VERSION 5.7 ;
BUSBITCHARS "[]" ;
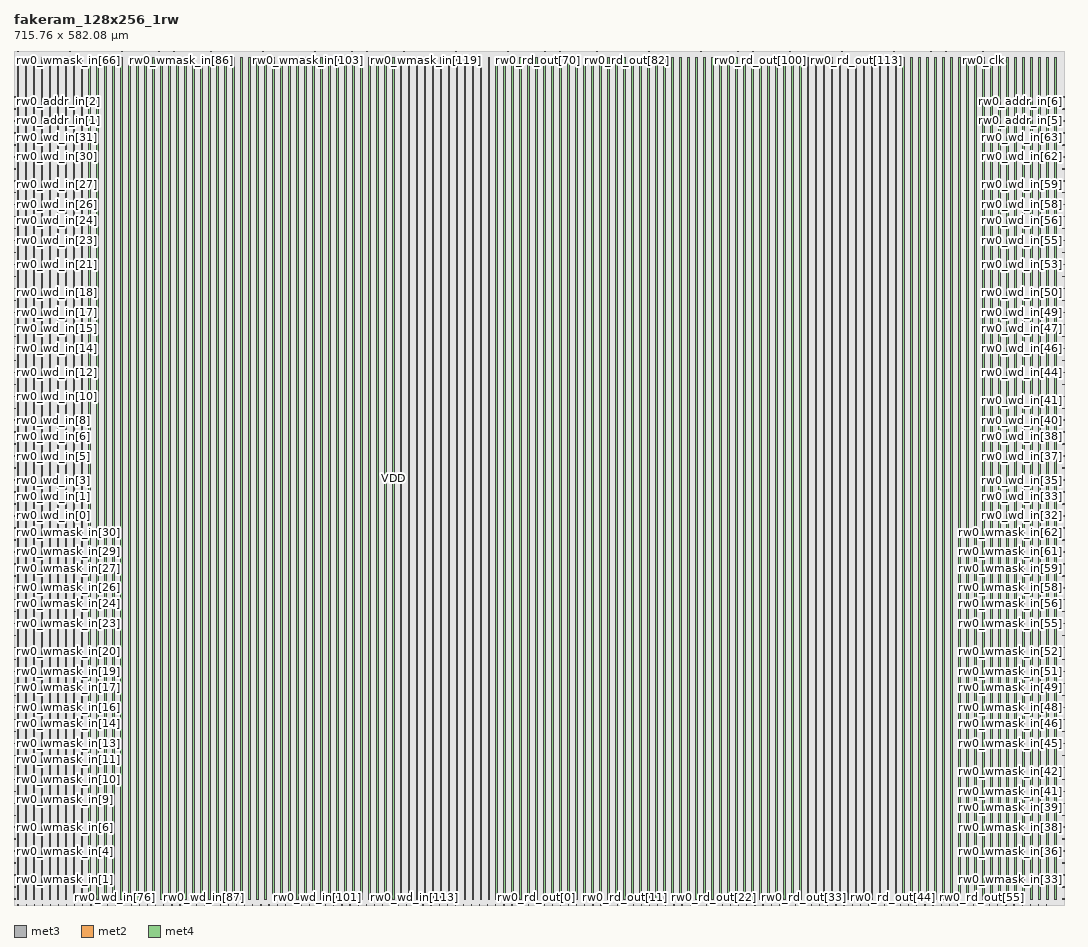
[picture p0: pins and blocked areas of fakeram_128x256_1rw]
MACRO fakeram_128x256_1rw
  FOREIGN fakeram_128x256_1rw 0 0 ;
  SYMMETRY X Y R90 ;
  SIZE 715.760 BY 582.080 ;
  CLASS BLOCK ;
  PIN rw0_wmask_in[0]
    DIRECTION INPUT ;
    USE SIGNAL ;
    SHAPE ABUTMENT ;
    PORT
      LAYER met3 ;
      RECT 0.000 3.930 0.900 4.230 ;
    END
  END rw0_wmask_in[0]
  PIN rw0_wmask_in[1]
    DIRECTION INPUT ;
    USE SIGNAL ;
    SHAPE ABUTMENT ;
    PORT
      LAYER met3 ;
      RECT 0.000 12.090 0.900 12.390 ;
    END
  END rw0_wmask_in[1]
  PIN rw0_wmask_in[2]
    DIRECTION INPUT ;
    USE SIGNAL ;
    SHAPE ABUTMENT ;
    PORT
      LAYER met3 ;
      RECT 0.000 20.250 0.900 20.550 ;
    END
  END rw0_wmask_in[2]
  PIN rw0_wmask_in[3]
    DIRECTION INPUT ;
    USE SIGNAL ;
    SHAPE ABUTMENT ;
    PORT
      LAYER met3 ;
      RECT 0.000 28.410 0.900 28.710 ;
    END
  END rw0_wmask_in[3]
  PIN rw0_wmask_in[4]
    DIRECTION INPUT ;
    USE SIGNAL ;
    SHAPE ABUTMENT ;
    PORT
      LAYER met3 ;
      RECT 0.000 36.570 0.900 36.870 ;
    END
  END rw0_wmask_in[4]
  PIN rw0_wmask_in[5]
    DIRECTION INPUT ;
    USE SIGNAL ;
    SHAPE ABUTMENT ;
    PORT
      LAYER met3 ;
      RECT 0.000 44.730 0.900 45.030 ;
    END
  END rw0_wmask_in[5]
  PIN rw0_wmask_in[6]
    DIRECTION INPUT ;
    USE SIGNAL ;
    SHAPE ABUTMENT ;
    PORT
      LAYER met3 ;
      RECT 0.000 52.890 0.900 53.190 ;
    END
  END rw0_wmask_in[6]
  PIN rw0_wmask_in[7]
    DIRECTION INPUT ;
    USE SIGNAL ;
    SHAPE ABUTMENT ;
    PORT
      LAYER met3 ;
      RECT 0.000 61.050 0.900 61.350 ;
    END
  END rw0_wmask_in[7]
  PIN rw0_wmask_in[8]
    DIRECTION INPUT ;
    USE SIGNAL ;
    SHAPE ABUTMENT ;
    PORT
      LAYER met3 ;
      RECT 0.000 69.210 0.900 69.510 ;
    END
  END rw0_wmask_in[8]
  PIN rw0_wmask_in[9]
    DIRECTION INPUT ;
    USE SIGNAL ;
    SHAPE ABUTMENT ;
    PORT
      LAYER met3 ;
      RECT 0.000 77.370 0.900 77.670 ;
    END
  END rw0_wmask_in[9]
  PIN rw0_wmask_in[10]
    DIRECTION INPUT ;
    USE SIGNAL ;
    SHAPE ABUTMENT ;
    PORT
      LAYER met3 ;
      RECT 0.000 85.530 0.900 85.830 ;
    END
  END rw0_wmask_in[10]
  PIN rw0_wmask_in[11]
    DIRECTION INPUT ;
    USE SIGNAL ;
    SHAPE ABUTMENT ;
    PORT
      LAYER met3 ;
      RECT 0.000 93.690 0.900 93.990 ;
    END
  END rw0_wmask_in[11]
  PIN rw0_wmask_in[12]
    DIRECTION INPUT ;
    USE SIGNAL ;
    SHAPE ABUTMENT ;
    PORT
      LAYER met3 ;
      RECT 0.000 101.850 0.900 102.150 ;
    END
  END rw0_wmask_in[12]
  PIN rw0_wmask_in[13]
    DIRECTION INPUT ;
    USE SIGNAL ;
    SHAPE ABUTMENT ;
    PORT
      LAYER met3 ;
      RECT 0.000 110.010 0.900 110.310 ;
    END
  END rw0_wmask_in[13]
  PIN rw0_wmask_in[14]
    DIRECTION INPUT ;
    USE SIGNAL ;
    SHAPE ABUTMENT ;
    PORT
      LAYER met3 ;
      RECT 0.000 118.170 0.900 118.470 ;
    END
  END rw0_wmask_in[14]
  PIN rw0_wmask_in[15]
    DIRECTION INPUT ;
    USE SIGNAL ;
    SHAPE ABUTMENT ;
    PORT
      LAYER met3 ;
      RECT 0.000 126.330 0.900 126.630 ;
    END
  END rw0_wmask_in[15]
  PIN rw0_wmask_in[16]
    DIRECTION INPUT ;
    USE SIGNAL ;
    SHAPE ABUTMENT ;
    PORT
      LAYER met3 ;
      RECT 0.000 134.490 0.900 134.790 ;
    END
  END rw0_wmask_in[16]
  PIN rw0_wmask_in[17]
    DIRECTION INPUT ;
    USE SIGNAL ;
    SHAPE ABUTMENT ;
    PORT
      LAYER met3 ;
      RECT 0.000 142.650 0.900 142.950 ;
    END
  END rw0_wmask_in[17]
  PIN rw0_wmask_in[18]
    DIRECTION INPUT ;
    USE SIGNAL ;
    SHAPE ABUTMENT ;
    PORT
      LAYER met3 ;
      RECT 0.000 150.810 0.900 151.110 ;
    END
  END rw0_wmask_in[18]
  PIN rw0_wmask_in[19]
    DIRECTION INPUT ;
    USE SIGNAL ;
    SHAPE ABUTMENT ;
    PORT
      LAYER met3 ;
      RECT 0.000 158.970 0.900 159.270 ;
    END
  END rw0_wmask_in[19]
  PIN rw0_wmask_in[20]
    DIRECTION INPUT ;
    USE SIGNAL ;
    SHAPE ABUTMENT ;
    PORT
      LAYER met3 ;
      RECT 0.000 167.130 0.900 167.430 ;
    END
  END rw0_wmask_in[20]
  PIN rw0_wmask_in[21]
    DIRECTION INPUT ;
    USE SIGNAL ;
    SHAPE ABUTMENT ;
    PORT
      LAYER met3 ;
      RECT 0.000 175.290 0.900 175.590 ;
    END
  END rw0_wmask_in[21]
  PIN rw0_wmask_in[22]
    DIRECTION INPUT ;
    USE SIGNAL ;
    SHAPE ABUTMENT ;
    PORT
      LAYER met3 ;
      RECT 0.000 183.450 0.900 183.750 ;
    END
  END rw0_wmask_in[22]
  PIN rw0_wmask_in[23]
    DIRECTION INPUT ;
    USE SIGNAL ;
    SHAPE ABUTMENT ;
    PORT
      LAYER met3 ;
      RECT 0.000 191.610 0.900 191.910 ;
    END
  END rw0_wmask_in[23]
  PIN rw0_wmask_in[24]
    DIRECTION INPUT ;
    USE SIGNAL ;
    SHAPE ABUTMENT ;
    PORT
      LAYER met3 ;
      RECT 0.000 199.770 0.900 200.070 ;
    END
  END rw0_wmask_in[24]
  PIN rw0_wmask_in[25]
    DIRECTION INPUT ;
    USE SIGNAL ;
    SHAPE ABUTMENT ;
    PORT
      LAYER met3 ;
      RECT 0.000 207.930 0.900 208.230 ;
    END
  END rw0_wmask_in[25]
  PIN rw0_wmask_in[26]
    DIRECTION INPUT ;
    USE SIGNAL ;
    SHAPE ABUTMENT ;
    PORT
      LAYER met3 ;
      RECT 0.000 216.090 0.900 216.390 ;
    END
  END rw0_wmask_in[26]
  PIN rw0_wmask_in[27]
    DIRECTION INPUT ;
    USE SIGNAL ;
    SHAPE ABUTMENT ;
    PORT
      LAYER met3 ;
      RECT 0.000 224.250 0.900 224.550 ;
    END
  END rw0_wmask_in[27]
  PIN rw0_wmask_in[28]
    DIRECTION INPUT ;
    USE SIGNAL ;
    SHAPE ABUTMENT ;
    PORT
      LAYER met3 ;
      RECT 0.000 232.410 0.900 232.710 ;
    END
  END rw0_wmask_in[28]
  PIN rw0_wmask_in[29]
    DIRECTION INPUT ;
    USE SIGNAL ;
    SHAPE ABUTMENT ;
    PORT
      LAYER met3 ;
      RECT 0.000 240.570 0.900 240.870 ;
    END
  END rw0_wmask_in[29]
  PIN rw0_wmask_in[30]
    DIRECTION INPUT ;
    USE SIGNAL ;
    SHAPE ABUTMENT ;
    PORT
      LAYER met3 ;
      RECT 0.000 248.730 0.900 249.030 ;
    END
  END rw0_wmask_in[30]
  PIN rw0_wmask_in[31]
    DIRECTION INPUT ;
    USE SIGNAL ;
    SHAPE ABUTMENT ;
    PORT
      LAYER met3 ;
      RECT 0.000 256.890 0.900 257.190 ;
    END
  END rw0_wmask_in[31]
  PIN rw0_wmask_in[32]
    DIRECTION INPUT ;
    USE SIGNAL ;
    SHAPE ABUTMENT ;
    PORT
      LAYER met3 ;
      RECT 714.860 3.930 715.760 4.230 ;
    END
  END rw0_wmask_in[32]
  PIN rw0_wmask_in[33]
    DIRECTION INPUT ;
    USE SIGNAL ;
    SHAPE ABUTMENT ;
    PORT
      LAYER met3 ;
      RECT 714.860 12.090 715.760 12.390 ;
    END
  END rw0_wmask_in[33]
  PIN rw0_wmask_in[34]
    DIRECTION INPUT ;
    USE SIGNAL ;
    SHAPE ABUTMENT ;
    PORT
      LAYER met3 ;
      RECT 714.860 20.250 715.760 20.550 ;
    END
  END rw0_wmask_in[34]
  PIN rw0_wmask_in[35]
    DIRECTION INPUT ;
    USE SIGNAL ;
    SHAPE ABUTMENT ;
    PORT
      LAYER met3 ;
      RECT 714.860 28.410 715.760 28.710 ;
    END
  END rw0_wmask_in[35]
  PIN rw0_wmask_in[36]
    DIRECTION INPUT ;
    USE SIGNAL ;
    SHAPE ABUTMENT ;
    PORT
      LAYER met3 ;
      RECT 714.860 36.570 715.760 36.870 ;
    END
  END rw0_wmask_in[36]
  PIN rw0_wmask_in[37]
    DIRECTION INPUT ;
    USE SIGNAL ;
    SHAPE ABUTMENT ;
    PORT
      LAYER met3 ;
      RECT 714.860 44.730 715.760 45.030 ;
    END
  END rw0_wmask_in[37]
  PIN rw0_wmask_in[38]
    DIRECTION INPUT ;
    USE SIGNAL ;
    SHAPE ABUTMENT ;
    PORT
      LAYER met3 ;
      RECT 714.860 52.890 715.760 53.190 ;
    END
  END rw0_wmask_in[38]
  PIN rw0_wmask_in[39]
    DIRECTION INPUT ;
    USE SIGNAL ;
    SHAPE ABUTMENT ;
    PORT
      LAYER met3 ;
      RECT 714.860 61.050 715.760 61.350 ;
    END
  END rw0_wmask_in[39]
  PIN rw0_wmask_in[40]
    DIRECTION INPUT ;
    USE SIGNAL ;
    SHAPE ABUTMENT ;
    PORT
      LAYER met3 ;
      RECT 714.860 69.210 715.760 69.510 ;
    END
  END rw0_wmask_in[40]
  PIN rw0_wmask_in[41]
    DIRECTION INPUT ;
    USE SIGNAL ;
    SHAPE ABUTMENT ;
    PORT
      LAYER met3 ;
      RECT 714.860 77.370 715.760 77.670 ;
    END
  END rw0_wmask_in[41]
  PIN rw0_wmask_in[42]
    DIRECTION INPUT ;
    USE SIGNAL ;
    SHAPE ABUTMENT ;
    PORT
      LAYER met3 ;
      RECT 714.860 85.530 715.760 85.830 ;
    END
  END rw0_wmask_in[42]
  PIN rw0_wmask_in[43]
    DIRECTION INPUT ;
    USE SIGNAL ;
    SHAPE ABUTMENT ;
    PORT
      LAYER met3 ;
      RECT 714.860 93.690 715.760 93.990 ;
    END
  END rw0_wmask_in[43]
  PIN rw0_wmask_in[44]
    DIRECTION INPUT ;
    USE SIGNAL ;
    SHAPE ABUTMENT ;
    PORT
      LAYER met3 ;
      RECT 714.860 101.850 715.760 102.150 ;
    END
  END rw0_wmask_in[44]
  PIN rw0_wmask_in[45]
    DIRECTION INPUT ;
    USE SIGNAL ;
    SHAPE ABUTMENT ;
    PORT
      LAYER met3 ;
      RECT 714.860 110.010 715.760 110.310 ;
    END
  END rw0_wmask_in[45]
  PIN rw0_wmask_in[46]
    DIRECTION INPUT ;
    USE SIGNAL ;
    SHAPE ABUTMENT ;
    PORT
      LAYER met3 ;
      RECT 714.860 118.170 715.760 118.470 ;
    END
  END rw0_wmask_in[46]
  PIN rw0_wmask_in[47]
    DIRECTION INPUT ;
    USE SIGNAL ;
    SHAPE ABUTMENT ;
    PORT
      LAYER met3 ;
      RECT 714.860 126.330 715.760 126.630 ;
    END
  END rw0_wmask_in[47]
  PIN rw0_wmask_in[48]
    DIRECTION INPUT ;
    USE SIGNAL ;
    SHAPE ABUTMENT ;
    PORT
      LAYER met3 ;
      RECT 714.860 134.490 715.760 134.790 ;
    END
  END rw0_wmask_in[48]
  PIN rw0_wmask_in[49]
    DIRECTION INPUT ;
    USE SIGNAL ;
    SHAPE ABUTMENT ;
    PORT
      LAYER met3 ;
      RECT 714.860 142.650 715.760 142.950 ;
    END
  END rw0_wmask_in[49]
  PIN rw0_wmask_in[50]
    DIRECTION INPUT ;
    USE SIGNAL ;
    SHAPE ABUTMENT ;
    PORT
      LAYER met3 ;
      RECT 714.860 150.810 715.760 151.110 ;
    END
  END rw0_wmask_in[50]
  PIN rw0_wmask_in[51]
    DIRECTION INPUT ;
    USE SIGNAL ;
    SHAPE ABUTMENT ;
    PORT
      LAYER met3 ;
      RECT 714.860 158.970 715.760 159.270 ;
    END
  END rw0_wmask_in[51]
  PIN rw0_wmask_in[52]
    DIRECTION INPUT ;
    USE SIGNAL ;
    SHAPE ABUTMENT ;
    PORT
      LAYER met3 ;
      RECT 714.860 167.130 715.760 167.430 ;
    END
  END rw0_wmask_in[52]
  PIN rw0_wmask_in[53]
    DIRECTION INPUT ;
    USE SIGNAL ;
    SHAPE ABUTMENT ;
    PORT
      LAYER met3 ;
      RECT 714.860 175.290 715.760 175.590 ;
    END
  END rw0_wmask_in[53]
  PIN rw0_wmask_in[54]
    DIRECTION INPUT ;
    USE SIGNAL ;
    SHAPE ABUTMENT ;
    PORT
      LAYER met3 ;
      RECT 714.860 183.450 715.760 183.750 ;
    END
  END rw0_wmask_in[54]
  PIN rw0_wmask_in[55]
    DIRECTION INPUT ;
    USE SIGNAL ;
    SHAPE ABUTMENT ;
    PORT
      LAYER met3 ;
      RECT 714.860 191.610 715.760 191.910 ;
    END
  END rw0_wmask_in[55]
  PIN rw0_wmask_in[56]
    DIRECTION INPUT ;
    USE SIGNAL ;
    SHAPE ABUTMENT ;
    PORT
      LAYER met3 ;
      RECT 714.860 199.770 715.760 200.070 ;
    END
  END rw0_wmask_in[56]
  PIN rw0_wmask_in[57]
    DIRECTION INPUT ;
    USE SIGNAL ;
    SHAPE ABUTMENT ;
    PORT
      LAYER met3 ;
      RECT 714.860 207.930 715.760 208.230 ;
    END
  END rw0_wmask_in[57]
  PIN rw0_wmask_in[58]
    DIRECTION INPUT ;
    USE SIGNAL ;
    SHAPE ABUTMENT ;
    PORT
      LAYER met3 ;
      RECT 714.860 216.090 715.760 216.390 ;
    END
  END rw0_wmask_in[58]
  PIN rw0_wmask_in[59]
    DIRECTION INPUT ;
    USE SIGNAL ;
    SHAPE ABUTMENT ;
    PORT
      LAYER met3 ;
      RECT 714.860 224.250 715.760 224.550 ;
    END
  END rw0_wmask_in[59]
  PIN rw0_wmask_in[60]
    DIRECTION INPUT ;
    USE SIGNAL ;
    SHAPE ABUTMENT ;
    PORT
      LAYER met3 ;
      RECT 714.860 232.410 715.760 232.710 ;
    END
  END rw0_wmask_in[60]
  PIN rw0_wmask_in[61]
    DIRECTION INPUT ;
    USE SIGNAL ;
    SHAPE ABUTMENT ;
    PORT
      LAYER met3 ;
      RECT 714.860 240.570 715.760 240.870 ;
    END
  END rw0_wmask_in[61]
  PIN rw0_wmask_in[62]
    DIRECTION INPUT ;
    USE SIGNAL ;
    SHAPE ABUTMENT ;
    PORT
      LAYER met3 ;
      RECT 714.860 248.730 715.760 249.030 ;
    END
  END rw0_wmask_in[62]
  PIN rw0_wmask_in[63]
    DIRECTION INPUT ;
    USE SIGNAL ;
    SHAPE ABUTMENT ;
    PORT
      LAYER met3 ;
      RECT 714.860 256.890 715.760 257.190 ;
    END
  END rw0_wmask_in[63]
  PIN rw0_wmask_in[64]
    DIRECTION INPUT ;
    USE SIGNAL ;
    SHAPE ABUTMENT ;
    PORT
      LAYER met2 ;
      RECT 2.690 581.660 2.830 582.080 ;
    END
  END rw0_wmask_in[64]
  PIN rw0_wmask_in[65]
    DIRECTION INPUT ;
    USE SIGNAL ;
    SHAPE ABUTMENT ;
    PORT
      LAYER met2 ;
      RECT 7.750 581.660 7.890 582.080 ;
    END
  END rw0_wmask_in[65]
  PIN rw0_wmask_in[66]
    DIRECTION INPUT ;
    USE SIGNAL ;
    SHAPE ABUTMENT ;
    PORT
      LAYER met2 ;
      RECT 12.810 581.660 12.950 582.080 ;
    END
  END rw0_wmask_in[66]
  PIN rw0_wmask_in[67]
    DIRECTION INPUT ;
    USE SIGNAL ;
    SHAPE ABUTMENT ;
    PORT
      LAYER met2 ;
      RECT 17.870 581.660 18.010 582.080 ;
    END
  END rw0_wmask_in[67]
  PIN rw0_wmask_in[68]
    DIRECTION INPUT ;
    USE SIGNAL ;
    SHAPE ABUTMENT ;
    PORT
      LAYER met2 ;
      RECT 22.930 581.660 23.070 582.080 ;
    END
  END rw0_wmask_in[68]
  PIN rw0_wmask_in[69]
    DIRECTION INPUT ;
    USE SIGNAL ;
    SHAPE ABUTMENT ;
    PORT
      LAYER met2 ;
      RECT 27.990 581.660 28.130 582.080 ;
    END
  END rw0_wmask_in[69]
  PIN rw0_wmask_in[70]
    DIRECTION INPUT ;
    USE SIGNAL ;
    SHAPE ABUTMENT ;
    PORT
      LAYER met2 ;
      RECT 33.050 581.660 33.190 582.080 ;
    END
  END rw0_wmask_in[70]
  PIN rw0_wmask_in[71]
    DIRECTION INPUT ;
    USE SIGNAL ;
    SHAPE ABUTMENT ;
    PORT
      LAYER met2 ;
      RECT 38.110 581.660 38.250 582.080 ;
    END
  END rw0_wmask_in[71]
  PIN rw0_wmask_in[72]
    DIRECTION INPUT ;
    USE SIGNAL ;
    SHAPE ABUTMENT ;
    PORT
      LAYER met2 ;
      RECT 43.170 581.660 43.310 582.080 ;
    END
  END rw0_wmask_in[72]
  PIN rw0_wmask_in[73]
    DIRECTION INPUT ;
    USE SIGNAL ;
    SHAPE ABUTMENT ;
    PORT
      LAYER met2 ;
      RECT 48.230 581.660 48.370 582.080 ;
    END
  END rw0_wmask_in[73]
  PIN rw0_wmask_in[74]
    DIRECTION INPUT ;
    USE SIGNAL ;
    SHAPE ABUTMENT ;
    PORT
      LAYER met2 ;
      RECT 53.290 581.660 53.430 582.080 ;
    END
  END rw0_wmask_in[74]
  PIN rw0_wmask_in[75]
    DIRECTION INPUT ;
    USE SIGNAL ;
    SHAPE ABUTMENT ;
    PORT
      LAYER met2 ;
      RECT 58.350 581.660 58.490 582.080 ;
    END
  END rw0_wmask_in[75]
  PIN rw0_wmask_in[76]
    DIRECTION INPUT ;
    USE SIGNAL ;
    SHAPE ABUTMENT ;
    PORT
      LAYER met2 ;
      RECT 63.410 581.660 63.550 582.080 ;
    END
  END rw0_wmask_in[76]
  PIN rw0_wmask_in[77]
    DIRECTION INPUT ;
    USE SIGNAL ;
    SHAPE ABUTMENT ;
    PORT
      LAYER met2 ;
      RECT 68.470 581.660 68.610 582.080 ;
    END
  END rw0_wmask_in[77]
  PIN rw0_wmask_in[78]
    DIRECTION INPUT ;
    USE SIGNAL ;
    SHAPE ABUTMENT ;
    PORT
      LAYER met2 ;
      RECT 73.530 581.660 73.670 582.080 ;
    END
  END rw0_wmask_in[78]
  PIN rw0_wmask_in[79]
    DIRECTION INPUT ;
    USE SIGNAL ;
    SHAPE ABUTMENT ;
    PORT
      LAYER met2 ;
      RECT 78.590 581.660 78.730 582.080 ;
    END
  END rw0_wmask_in[79]
  PIN rw0_wmask_in[80]
    DIRECTION INPUT ;
    USE SIGNAL ;
    SHAPE ABUTMENT ;
    PORT
      LAYER met2 ;
      RECT 83.650 581.660 83.790 582.080 ;
    END
  END rw0_wmask_in[80]
  PIN rw0_wmask_in[81]
    DIRECTION INPUT ;
    USE SIGNAL ;
    SHAPE ABUTMENT ;
    PORT
      LAYER met2 ;
      RECT 88.710 581.660 88.850 582.080 ;
    END
  END rw0_wmask_in[81]
  PIN rw0_wmask_in[82]
    DIRECTION INPUT ;
    USE SIGNAL ;
    SHAPE ABUTMENT ;
    PORT
      LAYER met2 ;
      RECT 93.770 581.660 93.910 582.080 ;
    END
  END rw0_wmask_in[82]
  PIN rw0_wmask_in[83]
    DIRECTION INPUT ;
    USE SIGNAL ;
    SHAPE ABUTMENT ;
    PORT
      LAYER met2 ;
      RECT 98.830 581.660 98.970 582.080 ;
    END
  END rw0_wmask_in[83]
  PIN rw0_wmask_in[84]
    DIRECTION INPUT ;
    USE SIGNAL ;
    SHAPE ABUTMENT ;
    PORT
      LAYER met2 ;
      RECT 103.890 581.660 104.030 582.080 ;
    END
  END rw0_wmask_in[84]
  PIN rw0_wmask_in[85]
    DIRECTION INPUT ;
    USE SIGNAL ;
    SHAPE ABUTMENT ;
    PORT
      LAYER met2 ;
      RECT 108.950 581.660 109.090 582.080 ;
    END
  END rw0_wmask_in[85]
  PIN rw0_wmask_in[86]
    DIRECTION INPUT ;
    USE SIGNAL ;
    SHAPE ABUTMENT ;
    PORT
      LAYER met2 ;
      RECT 114.010 581.660 114.150 582.080 ;
    END
  END rw0_wmask_in[86]
  PIN rw0_wmask_in[87]
    DIRECTION INPUT ;
    USE SIGNAL ;
    SHAPE ABUTMENT ;
    PORT
      LAYER met2 ;
      RECT 119.070 581.660 119.210 582.080 ;
    END
  END rw0_wmask_in[87]
  PIN rw0_wmask_in[88]
    DIRECTION INPUT ;
    USE SIGNAL ;
    SHAPE ABUTMENT ;
    PORT
      LAYER met2 ;
      RECT 124.130 581.660 124.270 582.080 ;
    END
  END rw0_wmask_in[88]
  PIN rw0_wmask_in[89]
    DIRECTION INPUT ;
    USE SIGNAL ;
    SHAPE ABUTMENT ;
    PORT
      LAYER met2 ;
      RECT 129.190 581.660 129.330 582.080 ;
    END
  END rw0_wmask_in[89]
  PIN rw0_wmask_in[90]
    DIRECTION INPUT ;
    USE SIGNAL ;
    SHAPE ABUTMENT ;
    PORT
      LAYER met2 ;
      RECT 134.250 581.660 134.390 582.080 ;
    END
  END rw0_wmask_in[90]
  PIN rw0_wmask_in[91]
    DIRECTION INPUT ;
    USE SIGNAL ;
    SHAPE ABUTMENT ;
    PORT
      LAYER met2 ;
      RECT 139.310 581.660 139.450 582.080 ;
    END
  END rw0_wmask_in[91]
  PIN rw0_wmask_in[92]
    DIRECTION INPUT ;
    USE SIGNAL ;
    SHAPE ABUTMENT ;
    PORT
      LAYER met2 ;
      RECT 144.370 581.660 144.510 582.080 ;
    END
  END rw0_wmask_in[92]
  PIN rw0_wmask_in[93]
    DIRECTION INPUT ;
    USE SIGNAL ;
    SHAPE ABUTMENT ;
    PORT
      LAYER met2 ;
      RECT 149.430 581.660 149.570 582.080 ;
    END
  END rw0_wmask_in[93]
  PIN rw0_wmask_in[94]
    DIRECTION INPUT ;
    USE SIGNAL ;
    SHAPE ABUTMENT ;
    PORT
      LAYER met2 ;
      RECT 154.490 581.660 154.630 582.080 ;
    END
  END rw0_wmask_in[94]
  PIN rw0_wmask_in[95]
    DIRECTION INPUT ;
    USE SIGNAL ;
    SHAPE ABUTMENT ;
    PORT
      LAYER met2 ;
      RECT 159.550 581.660 159.690 582.080 ;
    END
  END rw0_wmask_in[95]
  PIN rw0_wmask_in[96]
    DIRECTION INPUT ;
    USE SIGNAL ;
    SHAPE ABUTMENT ;
    PORT
      LAYER met2 ;
      RECT 164.610 581.660 164.750 582.080 ;
    END
  END rw0_wmask_in[96]
  PIN rw0_wmask_in[97]
    DIRECTION INPUT ;
    USE SIGNAL ;
    SHAPE ABUTMENT ;
    PORT
      LAYER met2 ;
      RECT 169.670 581.660 169.810 582.080 ;
    END
  END rw0_wmask_in[97]
  PIN rw0_wmask_in[98]
    DIRECTION INPUT ;
    USE SIGNAL ;
    SHAPE ABUTMENT ;
    PORT
      LAYER met2 ;
      RECT 174.730 581.660 174.870 582.080 ;
    END
  END rw0_wmask_in[98]
  PIN rw0_wmask_in[99]
    DIRECTION INPUT ;
    USE SIGNAL ;
    SHAPE ABUTMENT ;
    PORT
      LAYER met2 ;
      RECT 179.790 581.660 179.930 582.080 ;
    END
  END rw0_wmask_in[99]
  PIN rw0_wmask_in[100]
    DIRECTION INPUT ;
    USE SIGNAL ;
    SHAPE ABUTMENT ;
    PORT
      LAYER met2 ;
      RECT 184.850 581.660 184.990 582.080 ;
    END
  END rw0_wmask_in[100]
  PIN rw0_wmask_in[101]
    DIRECTION INPUT ;
    USE SIGNAL ;
    SHAPE ABUTMENT ;
    PORT
      LAYER met2 ;
      RECT 189.910 581.660 190.050 582.080 ;
    END
  END rw0_wmask_in[101]
  PIN rw0_wmask_in[102]
    DIRECTION INPUT ;
    USE SIGNAL ;
    SHAPE ABUTMENT ;
    PORT
      LAYER met2 ;
      RECT 194.970 581.660 195.110 582.080 ;
    END
  END rw0_wmask_in[102]
  PIN rw0_wmask_in[103]
    DIRECTION INPUT ;
    USE SIGNAL ;
    SHAPE ABUTMENT ;
    PORT
      LAYER met2 ;
      RECT 200.030 581.660 200.170 582.080 ;
    END
  END rw0_wmask_in[103]
  PIN rw0_wmask_in[104]
    DIRECTION INPUT ;
    USE SIGNAL ;
    SHAPE ABUTMENT ;
    PORT
      LAYER met2 ;
      RECT 205.090 581.660 205.230 582.080 ;
    END
  END rw0_wmask_in[104]
  PIN rw0_wmask_in[105]
    DIRECTION INPUT ;
    USE SIGNAL ;
    SHAPE ABUTMENT ;
    PORT
      LAYER met2 ;
      RECT 210.150 581.660 210.290 582.080 ;
    END
  END rw0_wmask_in[105]
  PIN rw0_wmask_in[106]
    DIRECTION INPUT ;
    USE SIGNAL ;
    SHAPE ABUTMENT ;
    PORT
      LAYER met2 ;
      RECT 215.210 581.660 215.350 582.080 ;
    END
  END rw0_wmask_in[106]
  PIN rw0_wmask_in[107]
    DIRECTION INPUT ;
    USE SIGNAL ;
    SHAPE ABUTMENT ;
    PORT
      LAYER met2 ;
      RECT 220.270 581.660 220.410 582.080 ;
    END
  END rw0_wmask_in[107]
  PIN rw0_wmask_in[108]
    DIRECTION INPUT ;
    USE SIGNAL ;
    SHAPE ABUTMENT ;
    PORT
      LAYER met2 ;
      RECT 225.330 581.660 225.470 582.080 ;
    END
  END rw0_wmask_in[108]
  PIN rw0_wmask_in[109]
    DIRECTION INPUT ;
    USE SIGNAL ;
    SHAPE ABUTMENT ;
    PORT
      LAYER met2 ;
      RECT 230.390 581.660 230.530 582.080 ;
    END
  END rw0_wmask_in[109]
  PIN rw0_wmask_in[110]
    DIRECTION INPUT ;
    USE SIGNAL ;
    SHAPE ABUTMENT ;
    PORT
      LAYER met2 ;
      RECT 235.450 581.660 235.590 582.080 ;
    END
  END rw0_wmask_in[110]
  PIN rw0_wmask_in[111]
    DIRECTION INPUT ;
    USE SIGNAL ;
    SHAPE ABUTMENT ;
    PORT
      LAYER met2 ;
      RECT 240.510 581.660 240.650 582.080 ;
    END
  END rw0_wmask_in[111]
  PIN rw0_wmask_in[112]
    DIRECTION INPUT ;
    USE SIGNAL ;
    SHAPE ABUTMENT ;
    PORT
      LAYER met2 ;
      RECT 245.570 581.660 245.710 582.080 ;
    END
  END rw0_wmask_in[112]
  PIN rw0_wmask_in[113]
    DIRECTION INPUT ;
    USE SIGNAL ;
    SHAPE ABUTMENT ;
    PORT
      LAYER met2 ;
      RECT 250.630 581.660 250.770 582.080 ;
    END
  END rw0_wmask_in[113]
  PIN rw0_wmask_in[114]
    DIRECTION INPUT ;
    USE SIGNAL ;
    SHAPE ABUTMENT ;
    PORT
      LAYER met2 ;
      RECT 255.690 581.660 255.830 582.080 ;
    END
  END rw0_wmask_in[114]
  PIN rw0_wmask_in[115]
    DIRECTION INPUT ;
    USE SIGNAL ;
    SHAPE ABUTMENT ;
    PORT
      LAYER met2 ;
      RECT 260.750 581.660 260.890 582.080 ;
    END
  END rw0_wmask_in[115]
  PIN rw0_wmask_in[116]
    DIRECTION INPUT ;
    USE SIGNAL ;
    SHAPE ABUTMENT ;
    PORT
      LAYER met2 ;
      RECT 265.810 581.660 265.950 582.080 ;
    END
  END rw0_wmask_in[116]
  PIN rw0_wmask_in[117]
    DIRECTION INPUT ;
    USE SIGNAL ;
    SHAPE ABUTMENT ;
    PORT
      LAYER met2 ;
      RECT 270.870 581.660 271.010 582.080 ;
    END
  END rw0_wmask_in[117]
  PIN rw0_wmask_in[118]
    DIRECTION INPUT ;
    USE SIGNAL ;
    SHAPE ABUTMENT ;
    PORT
      LAYER met2 ;
      RECT 275.930 581.660 276.070 582.080 ;
    END
  END rw0_wmask_in[118]
  PIN rw0_wmask_in[119]
    DIRECTION INPUT ;
    USE SIGNAL ;
    SHAPE ABUTMENT ;
    PORT
      LAYER met2 ;
      RECT 280.990 581.660 281.130 582.080 ;
    END
  END rw0_wmask_in[119]
  PIN rw0_wmask_in[120]
    DIRECTION INPUT ;
    USE SIGNAL ;
    SHAPE ABUTMENT ;
    PORT
      LAYER met2 ;
      RECT 286.050 581.660 286.190 582.080 ;
    END
  END rw0_wmask_in[120]
  PIN rw0_wmask_in[121]
    DIRECTION INPUT ;
    USE SIGNAL ;
    SHAPE ABUTMENT ;
    PORT
      LAYER met2 ;
      RECT 291.110 581.660 291.250 582.080 ;
    END
  END rw0_wmask_in[121]
  PIN rw0_wmask_in[122]
    DIRECTION INPUT ;
    USE SIGNAL ;
    SHAPE ABUTMENT ;
    PORT
      LAYER met2 ;
      RECT 296.170 581.660 296.310 582.080 ;
    END
  END rw0_wmask_in[122]
  PIN rw0_wmask_in[123]
    DIRECTION INPUT ;
    USE SIGNAL ;
    SHAPE ABUTMENT ;
    PORT
      LAYER met2 ;
      RECT 301.230 581.660 301.370 582.080 ;
    END
  END rw0_wmask_in[123]
  PIN rw0_wmask_in[124]
    DIRECTION INPUT ;
    USE SIGNAL ;
    SHAPE ABUTMENT ;
    PORT
      LAYER met2 ;
      RECT 306.290 581.660 306.430 582.080 ;
    END
  END rw0_wmask_in[124]
  PIN rw0_wmask_in[125]
    DIRECTION INPUT ;
    USE SIGNAL ;
    SHAPE ABUTMENT ;
    PORT
      LAYER met2 ;
      RECT 311.350 581.660 311.490 582.080 ;
    END
  END rw0_wmask_in[125]
  PIN rw0_wmask_in[126]
    DIRECTION INPUT ;
    USE SIGNAL ;
    SHAPE ABUTMENT ;
    PORT
      LAYER met2 ;
      RECT 316.410 581.660 316.550 582.080 ;
    END
  END rw0_wmask_in[126]
  PIN rw0_wmask_in[127]
    DIRECTION INPUT ;
    USE SIGNAL ;
    SHAPE ABUTMENT ;
    PORT
      LAYER met2 ;
      RECT 321.470 581.660 321.610 582.080 ;
    END
  END rw0_wmask_in[127]
  PIN rw0_wd_in[0]
    DIRECTION INPUT ;
    USE SIGNAL ;
    SHAPE ABUTMENT ;
    PORT
      LAYER met3 ;
      RECT 0.000 265.050 0.900 265.350 ;
    END
  END rw0_wd_in[0]
  PIN rw0_wd_in[1]
    DIRECTION INPUT ;
    USE SIGNAL ;
    SHAPE ABUTMENT ;
    PORT
      LAYER met3 ;
      RECT 0.000 273.210 0.900 273.510 ;
    END
  END rw0_wd_in[1]
  PIN rw0_wd_in[2]
    DIRECTION INPUT ;
    USE SIGNAL ;
    SHAPE ABUTMENT ;
    PORT
      LAYER met3 ;
      RECT 0.000 281.370 0.900 281.670 ;
    END
  END rw0_wd_in[2]
  PIN rw0_wd_in[3]
    DIRECTION INPUT ;
    USE SIGNAL ;
    SHAPE ABUTMENT ;
    PORT
      LAYER met3 ;
      RECT 0.000 289.530 0.900 289.830 ;
    END
  END rw0_wd_in[3]
  PIN rw0_wd_in[4]
    DIRECTION INPUT ;
    USE SIGNAL ;
    SHAPE ABUTMENT ;
    PORT
      LAYER met3 ;
      RECT 0.000 297.690 0.900 297.990 ;
    END
  END rw0_wd_in[4]
  PIN rw0_wd_in[5]
    DIRECTION INPUT ;
    USE SIGNAL ;
    SHAPE ABUTMENT ;
    PORT
      LAYER met3 ;
      RECT 0.000 305.850 0.900 306.150 ;
    END
  END rw0_wd_in[5]
  PIN rw0_wd_in[6]
    DIRECTION INPUT ;
    USE SIGNAL ;
    SHAPE ABUTMENT ;
    PORT
      LAYER met3 ;
      RECT 0.000 314.010 0.900 314.310 ;
    END
  END rw0_wd_in[6]
  PIN rw0_wd_in[7]
    DIRECTION INPUT ;
    USE SIGNAL ;
    SHAPE ABUTMENT ;
    PORT
      LAYER met3 ;
      RECT 0.000 322.170 0.900 322.470 ;
    END
  END rw0_wd_in[7]
  PIN rw0_wd_in[8]
    DIRECTION INPUT ;
    USE SIGNAL ;
    SHAPE ABUTMENT ;
    PORT
      LAYER met3 ;
      RECT 0.000 330.330 0.900 330.630 ;
    END
  END rw0_wd_in[8]
  PIN rw0_wd_in[9]
    DIRECTION INPUT ;
    USE SIGNAL ;
    SHAPE ABUTMENT ;
    PORT
      LAYER met3 ;
      RECT 0.000 338.490 0.900 338.790 ;
    END
  END rw0_wd_in[9]
  PIN rw0_wd_in[10]
    DIRECTION INPUT ;
    USE SIGNAL ;
    SHAPE ABUTMENT ;
    PORT
      LAYER met3 ;
      RECT 0.000 346.650 0.900 346.950 ;
    END
  END rw0_wd_in[10]
  PIN rw0_wd_in[11]
    DIRECTION INPUT ;
    USE SIGNAL ;
    SHAPE ABUTMENT ;
    PORT
      LAYER met3 ;
      RECT 0.000 354.810 0.900 355.110 ;
    END
  END rw0_wd_in[11]
  PIN rw0_wd_in[12]
    DIRECTION INPUT ;
    USE SIGNAL ;
    SHAPE ABUTMENT ;
    PORT
      LAYER met3 ;
      RECT 0.000 362.970 0.900 363.270 ;
    END
  END rw0_wd_in[12]
  PIN rw0_wd_in[13]
    DIRECTION INPUT ;
    USE SIGNAL ;
    SHAPE ABUTMENT ;
    PORT
      LAYER met3 ;
      RECT 0.000 371.130 0.900 371.430 ;
    END
  END rw0_wd_in[13]
  PIN rw0_wd_in[14]
    DIRECTION INPUT ;
    USE SIGNAL ;
    SHAPE ABUTMENT ;
    PORT
      LAYER met3 ;
      RECT 0.000 379.290 0.900 379.590 ;
    END
  END rw0_wd_in[14]
  PIN rw0_wd_in[15]
    DIRECTION INPUT ;
    USE SIGNAL ;
    SHAPE ABUTMENT ;
    PORT
      LAYER met3 ;
      RECT 0.000 387.450 0.900 387.750 ;
    END
  END rw0_wd_in[15]
  PIN rw0_wd_in[16]
    DIRECTION INPUT ;
    USE SIGNAL ;
    SHAPE ABUTMENT ;
    PORT
      LAYER met3 ;
      RECT 0.000 395.610 0.900 395.910 ;
    END
  END rw0_wd_in[16]
  PIN rw0_wd_in[17]
    DIRECTION INPUT ;
    USE SIGNAL ;
    SHAPE ABUTMENT ;
    PORT
      LAYER met3 ;
      RECT 0.000 403.770 0.900 404.070 ;
    END
  END rw0_wd_in[17]
  PIN rw0_wd_in[18]
    DIRECTION INPUT ;
    USE SIGNAL ;
    SHAPE ABUTMENT ;
    PORT
      LAYER met3 ;
      RECT 0.000 411.930 0.900 412.230 ;
    END
  END rw0_wd_in[18]
  PIN rw0_wd_in[19]
    DIRECTION INPUT ;
    USE SIGNAL ;
    SHAPE ABUTMENT ;
    PORT
      LAYER met3 ;
      RECT 0.000 420.090 0.900 420.390 ;
    END
  END rw0_wd_in[19]
  PIN rw0_wd_in[20]
    DIRECTION INPUT ;
    USE SIGNAL ;
    SHAPE ABUTMENT ;
    PORT
      LAYER met3 ;
      RECT 0.000 428.250 0.900 428.550 ;
    END
  END rw0_wd_in[20]
  PIN rw0_wd_in[21]
    DIRECTION INPUT ;
    USE SIGNAL ;
    SHAPE ABUTMENT ;
    PORT
      LAYER met3 ;
      RECT 0.000 436.410 0.900 436.710 ;
    END
  END rw0_wd_in[21]
  PIN rw0_wd_in[22]
    DIRECTION INPUT ;
    USE SIGNAL ;
    SHAPE ABUTMENT ;
    PORT
      LAYER met3 ;
      RECT 0.000 444.570 0.900 444.870 ;
    END
  END rw0_wd_in[22]
  PIN rw0_wd_in[23]
    DIRECTION INPUT ;
    USE SIGNAL ;
    SHAPE ABUTMENT ;
    PORT
      LAYER met3 ;
      RECT 0.000 452.730 0.900 453.030 ;
    END
  END rw0_wd_in[23]
  PIN rw0_wd_in[24]
    DIRECTION INPUT ;
    USE SIGNAL ;
    SHAPE ABUTMENT ;
    PORT
      LAYER met3 ;
      RECT 0.000 460.890 0.900 461.190 ;
    END
  END rw0_wd_in[24]
  PIN rw0_wd_in[25]
    DIRECTION INPUT ;
    USE SIGNAL ;
    SHAPE ABUTMENT ;
    PORT
      LAYER met3 ;
      RECT 0.000 469.050 0.900 469.350 ;
    END
  END rw0_wd_in[25]
  PIN rw0_wd_in[26]
    DIRECTION INPUT ;
    USE SIGNAL ;
    SHAPE ABUTMENT ;
    PORT
      LAYER met3 ;
      RECT 0.000 477.210 0.900 477.510 ;
    END
  END rw0_wd_in[26]
  PIN rw0_wd_in[27]
    DIRECTION INPUT ;
    USE SIGNAL ;
    SHAPE ABUTMENT ;
    PORT
      LAYER met3 ;
      RECT 0.000 485.370 0.900 485.670 ;
    END
  END rw0_wd_in[27]
  PIN rw0_wd_in[28]
    DIRECTION INPUT ;
    USE SIGNAL ;
    SHAPE ABUTMENT ;
    PORT
      LAYER met3 ;
      RECT 0.000 493.530 0.900 493.830 ;
    END
  END rw0_wd_in[28]
  PIN rw0_wd_in[29]
    DIRECTION INPUT ;
    USE SIGNAL ;
    SHAPE ABUTMENT ;
    PORT
      LAYER met3 ;
      RECT 0.000 501.690 0.900 501.990 ;
    END
  END rw0_wd_in[29]
  PIN rw0_wd_in[30]
    DIRECTION INPUT ;
    USE SIGNAL ;
    SHAPE ABUTMENT ;
    PORT
      LAYER met3 ;
      RECT 0.000 509.850 0.900 510.150 ;
    END
  END rw0_wd_in[30]
  PIN rw0_wd_in[31]
    DIRECTION INPUT ;
    USE SIGNAL ;
    SHAPE ABUTMENT ;
    PORT
      LAYER met3 ;
      RECT 0.000 518.010 0.900 518.310 ;
    END
  END rw0_wd_in[31]
  PIN rw0_wd_in[32]
    DIRECTION INPUT ;
    USE SIGNAL ;
    SHAPE ABUTMENT ;
    PORT
      LAYER met3 ;
      RECT 714.860 265.050 715.760 265.350 ;
    END
  END rw0_wd_in[32]
  PIN rw0_wd_in[33]
    DIRECTION INPUT ;
    USE SIGNAL ;
    SHAPE ABUTMENT ;
    PORT
      LAYER met3 ;
      RECT 714.860 273.210 715.760 273.510 ;
    END
  END rw0_wd_in[33]
  PIN rw0_wd_in[34]
    DIRECTION INPUT ;
    USE SIGNAL ;
    SHAPE ABUTMENT ;
    PORT
      LAYER met3 ;
      RECT 714.860 281.370 715.760 281.670 ;
    END
  END rw0_wd_in[34]
  PIN rw0_wd_in[35]
    DIRECTION INPUT ;
    USE SIGNAL ;
    SHAPE ABUTMENT ;
    PORT
      LAYER met3 ;
      RECT 714.860 289.530 715.760 289.830 ;
    END
  END rw0_wd_in[35]
  PIN rw0_wd_in[36]
    DIRECTION INPUT ;
    USE SIGNAL ;
    SHAPE ABUTMENT ;
    PORT
      LAYER met3 ;
      RECT 714.860 297.690 715.760 297.990 ;
    END
  END rw0_wd_in[36]
  PIN rw0_wd_in[37]
    DIRECTION INPUT ;
    USE SIGNAL ;
    SHAPE ABUTMENT ;
    PORT
      LAYER met3 ;
      RECT 714.860 305.850 715.760 306.150 ;
    END
  END rw0_wd_in[37]
  PIN rw0_wd_in[38]
    DIRECTION INPUT ;
    USE SIGNAL ;
    SHAPE ABUTMENT ;
    PORT
      LAYER met3 ;
      RECT 714.860 314.010 715.760 314.310 ;
    END
  END rw0_wd_in[38]
  PIN rw0_wd_in[39]
    DIRECTION INPUT ;
    USE SIGNAL ;
    SHAPE ABUTMENT ;
    PORT
      LAYER met3 ;
      RECT 714.860 322.170 715.760 322.470 ;
    END
  END rw0_wd_in[39]
  PIN rw0_wd_in[40]
    DIRECTION INPUT ;
    USE SIGNAL ;
    SHAPE ABUTMENT ;
    PORT
      LAYER met3 ;
      RECT 714.860 330.330 715.760 330.630 ;
    END
  END rw0_wd_in[40]
  PIN rw0_wd_in[41]
    DIRECTION INPUT ;
    USE SIGNAL ;
    SHAPE ABUTMENT ;
    PORT
      LAYER met3 ;
      RECT 714.860 338.490 715.760 338.790 ;
    END
  END rw0_wd_in[41]
  PIN rw0_wd_in[42]
    DIRECTION INPUT ;
    USE SIGNAL ;
    SHAPE ABUTMENT ;
    PORT
      LAYER met3 ;
      RECT 714.860 346.650 715.760 346.950 ;
    END
  END rw0_wd_in[42]
  PIN rw0_wd_in[43]
    DIRECTION INPUT ;
    USE SIGNAL ;
    SHAPE ABUTMENT ;
    PORT
      LAYER met3 ;
      RECT 714.860 354.810 715.760 355.110 ;
    END
  END rw0_wd_in[43]
  PIN rw0_wd_in[44]
    DIRECTION INPUT ;
    USE SIGNAL ;
    SHAPE ABUTMENT ;
    PORT
      LAYER met3 ;
      RECT 714.860 362.970 715.760 363.270 ;
    END
  END rw0_wd_in[44]
  PIN rw0_wd_in[45]
    DIRECTION INPUT ;
    USE SIGNAL ;
    SHAPE ABUTMENT ;
    PORT
      LAYER met3 ;
      RECT 714.860 371.130 715.760 371.430 ;
    END
  END rw0_wd_in[45]
  PIN rw0_wd_in[46]
    DIRECTION INPUT ;
    USE SIGNAL ;
    SHAPE ABUTMENT ;
    PORT
      LAYER met3 ;
      RECT 714.860 379.290 715.760 379.590 ;
    END
  END rw0_wd_in[46]
  PIN rw0_wd_in[47]
    DIRECTION INPUT ;
    USE SIGNAL ;
    SHAPE ABUTMENT ;
    PORT
      LAYER met3 ;
      RECT 714.860 387.450 715.760 387.750 ;
    END
  END rw0_wd_in[47]
  PIN rw0_wd_in[48]
    DIRECTION INPUT ;
    USE SIGNAL ;
    SHAPE ABUTMENT ;
    PORT
      LAYER met3 ;
      RECT 714.860 395.610 715.760 395.910 ;
    END
  END rw0_wd_in[48]
  PIN rw0_wd_in[49]
    DIRECTION INPUT ;
    USE SIGNAL ;
    SHAPE ABUTMENT ;
    PORT
      LAYER met3 ;
      RECT 714.860 403.770 715.760 404.070 ;
    END
  END rw0_wd_in[49]
  PIN rw0_wd_in[50]
    DIRECTION INPUT ;
    USE SIGNAL ;
    SHAPE ABUTMENT ;
    PORT
      LAYER met3 ;
      RECT 714.860 411.930 715.760 412.230 ;
    END
  END rw0_wd_in[50]
  PIN rw0_wd_in[51]
    DIRECTION INPUT ;
    USE SIGNAL ;
    SHAPE ABUTMENT ;
    PORT
      LAYER met3 ;
      RECT 714.860 420.090 715.760 420.390 ;
    END
  END rw0_wd_in[51]
  PIN rw0_wd_in[52]
    DIRECTION INPUT ;
    USE SIGNAL ;
    SHAPE ABUTMENT ;
    PORT
      LAYER met3 ;
      RECT 714.860 428.250 715.760 428.550 ;
    END
  END rw0_wd_in[52]
  PIN rw0_wd_in[53]
    DIRECTION INPUT ;
    USE SIGNAL ;
    SHAPE ABUTMENT ;
    PORT
      LAYER met3 ;
      RECT 714.860 436.410 715.760 436.710 ;
    END
  END rw0_wd_in[53]
  PIN rw0_wd_in[54]
    DIRECTION INPUT ;
    USE SIGNAL ;
    SHAPE ABUTMENT ;
    PORT
      LAYER met3 ;
      RECT 714.860 444.570 715.760 444.870 ;
    END
  END rw0_wd_in[54]
  PIN rw0_wd_in[55]
    DIRECTION INPUT ;
    USE SIGNAL ;
    SHAPE ABUTMENT ;
    PORT
      LAYER met3 ;
      RECT 714.860 452.730 715.760 453.030 ;
    END
  END rw0_wd_in[55]
  PIN rw0_wd_in[56]
    DIRECTION INPUT ;
    USE SIGNAL ;
    SHAPE ABUTMENT ;
    PORT
      LAYER met3 ;
      RECT 714.860 460.890 715.760 461.190 ;
    END
  END rw0_wd_in[56]
  PIN rw0_wd_in[57]
    DIRECTION INPUT ;
    USE SIGNAL ;
    SHAPE ABUTMENT ;
    PORT
      LAYER met3 ;
      RECT 714.860 469.050 715.760 469.350 ;
    END
  END rw0_wd_in[57]
  PIN rw0_wd_in[58]
    DIRECTION INPUT ;
    USE SIGNAL ;
    SHAPE ABUTMENT ;
    PORT
      LAYER met3 ;
      RECT 714.860 477.210 715.760 477.510 ;
    END
  END rw0_wd_in[58]
  PIN rw0_wd_in[59]
    DIRECTION INPUT ;
    USE SIGNAL ;
    SHAPE ABUTMENT ;
    PORT
      LAYER met3 ;
      RECT 714.860 485.370 715.760 485.670 ;
    END
  END rw0_wd_in[59]
  PIN rw0_wd_in[60]
    DIRECTION INPUT ;
    USE SIGNAL ;
    SHAPE ABUTMENT ;
    PORT
      LAYER met3 ;
      RECT 714.860 493.530 715.760 493.830 ;
    END
  END rw0_wd_in[60]
  PIN rw0_wd_in[61]
    DIRECTION INPUT ;
    USE SIGNAL ;
    SHAPE ABUTMENT ;
    PORT
      LAYER met3 ;
      RECT 714.860 501.690 715.760 501.990 ;
    END
  END rw0_wd_in[61]
  PIN rw0_wd_in[62]
    DIRECTION INPUT ;
    USE SIGNAL ;
    SHAPE ABUTMENT ;
    PORT
      LAYER met3 ;
      RECT 714.860 509.850 715.760 510.150 ;
    END
  END rw0_wd_in[62]
  PIN rw0_wd_in[63]
    DIRECTION INPUT ;
    USE SIGNAL ;
    SHAPE ABUTMENT ;
    PORT
      LAYER met3 ;
      RECT 714.860 518.010 715.760 518.310 ;
    END
  END rw0_wd_in[63]
  PIN rw0_wd_in[64]
    DIRECTION INPUT ;
    USE SIGNAL ;
    SHAPE ABUTMENT ;
    PORT
      LAYER met2 ;
      RECT 2.690 0.000 2.830 0.420 ;
    END
  END rw0_wd_in[64]
  PIN rw0_wd_in[65]
    DIRECTION INPUT ;
    USE SIGNAL ;
    SHAPE ABUTMENT ;
    PORT
      LAYER met2 ;
      RECT 8.210 0.000 8.350 0.420 ;
    END
  END rw0_wd_in[65]
  PIN rw0_wd_in[66]
    DIRECTION INPUT ;
    USE SIGNAL ;
    SHAPE ABUTMENT ;
    PORT
      LAYER met2 ;
      RECT 13.730 0.000 13.870 0.420 ;
    END
  END rw0_wd_in[66]
  PIN rw0_wd_in[67]
    DIRECTION INPUT ;
    USE SIGNAL ;
    SHAPE ABUTMENT ;
    PORT
      LAYER met2 ;
      RECT 19.250 0.000 19.390 0.420 ;
    END
  END rw0_wd_in[67]
  PIN rw0_wd_in[68]
    DIRECTION INPUT ;
    USE SIGNAL ;
    SHAPE ABUTMENT ;
    PORT
      LAYER met2 ;
      RECT 24.770 0.000 24.910 0.420 ;
    END
  END rw0_wd_in[68]
  PIN rw0_wd_in[69]
    DIRECTION INPUT ;
    USE SIGNAL ;
    SHAPE ABUTMENT ;
    PORT
      LAYER met2 ;
      RECT 30.290 0.000 30.430 0.420 ;
    END
  END rw0_wd_in[69]
  PIN rw0_wd_in[70]
    DIRECTION INPUT ;
    USE SIGNAL ;
    SHAPE ABUTMENT ;
    PORT
      LAYER met2 ;
      RECT 35.810 0.000 35.950 0.420 ;
    END
  END rw0_wd_in[70]
  PIN rw0_wd_in[71]
    DIRECTION INPUT ;
    USE SIGNAL ;
    SHAPE ABUTMENT ;
    PORT
      LAYER met2 ;
      RECT 41.330 0.000 41.470 0.420 ;
    END
  END rw0_wd_in[71]
  PIN rw0_wd_in[72]
    DIRECTION INPUT ;
    USE SIGNAL ;
    SHAPE ABUTMENT ;
    PORT
      LAYER met2 ;
      RECT 46.850 0.000 46.990 0.420 ;
    END
  END rw0_wd_in[72]
  PIN rw0_wd_in[73]
    DIRECTION INPUT ;
    USE SIGNAL ;
    SHAPE ABUTMENT ;
    PORT
      LAYER met2 ;
      RECT 52.370 0.000 52.510 0.420 ;
    END
  END rw0_wd_in[73]
  PIN rw0_wd_in[74]
    DIRECTION INPUT ;
    USE SIGNAL ;
    SHAPE ABUTMENT ;
    PORT
      LAYER met2 ;
      RECT 57.890 0.000 58.030 0.420 ;
    END
  END rw0_wd_in[74]
  PIN rw0_wd_in[75]
    DIRECTION INPUT ;
    USE SIGNAL ;
    SHAPE ABUTMENT ;
    PORT
      LAYER met2 ;
      RECT 63.410 0.000 63.550 0.420 ;
    END
  END rw0_wd_in[75]
  PIN rw0_wd_in[76]
    DIRECTION INPUT ;
    USE SIGNAL ;
    SHAPE ABUTMENT ;
    PORT
      LAYER met2 ;
      RECT 68.930 0.000 69.070 0.420 ;
    END
  END rw0_wd_in[76]
  PIN rw0_wd_in[77]
    DIRECTION INPUT ;
    USE SIGNAL ;
    SHAPE ABUTMENT ;
    PORT
      LAYER met2 ;
      RECT 74.450 0.000 74.590 0.420 ;
    END
  END rw0_wd_in[77]
  PIN rw0_wd_in[78]
    DIRECTION INPUT ;
    USE SIGNAL ;
    SHAPE ABUTMENT ;
    PORT
      LAYER met2 ;
      RECT 79.970 0.000 80.110 0.420 ;
    END
  END rw0_wd_in[78]
  PIN rw0_wd_in[79]
    DIRECTION INPUT ;
    USE SIGNAL ;
    SHAPE ABUTMENT ;
    PORT
      LAYER met2 ;
      RECT 85.490 0.000 85.630 0.420 ;
    END
  END rw0_wd_in[79]
  PIN rw0_wd_in[80]
    DIRECTION INPUT ;
    USE SIGNAL ;
    SHAPE ABUTMENT ;
    PORT
      LAYER met2 ;
      RECT 91.010 0.000 91.150 0.420 ;
    END
  END rw0_wd_in[80]
  PIN rw0_wd_in[81]
    DIRECTION INPUT ;
    USE SIGNAL ;
    SHAPE ABUTMENT ;
    PORT
      LAYER met2 ;
      RECT 96.530 0.000 96.670 0.420 ;
    END
  END rw0_wd_in[81]
  PIN rw0_wd_in[82]
    DIRECTION INPUT ;
    USE SIGNAL ;
    SHAPE ABUTMENT ;
    PORT
      LAYER met2 ;
      RECT 102.050 0.000 102.190 0.420 ;
    END
  END rw0_wd_in[82]
  PIN rw0_wd_in[83]
    DIRECTION INPUT ;
    USE SIGNAL ;
    SHAPE ABUTMENT ;
    PORT
      LAYER met2 ;
      RECT 107.570 0.000 107.710 0.420 ;
    END
  END rw0_wd_in[83]
  PIN rw0_wd_in[84]
    DIRECTION INPUT ;
    USE SIGNAL ;
    SHAPE ABUTMENT ;
    PORT
      LAYER met2 ;
      RECT 113.090 0.000 113.230 0.420 ;
    END
  END rw0_wd_in[84]
  PIN rw0_wd_in[85]
    DIRECTION INPUT ;
    USE SIGNAL ;
    SHAPE ABUTMENT ;
    PORT
      LAYER met2 ;
      RECT 118.610 0.000 118.750 0.420 ;
    END
  END rw0_wd_in[85]
  PIN rw0_wd_in[86]
    DIRECTION INPUT ;
    USE SIGNAL ;
    SHAPE ABUTMENT ;
    PORT
      LAYER met2 ;
      RECT 124.130 0.000 124.270 0.420 ;
    END
  END rw0_wd_in[86]
  PIN rw0_wd_in[87]
    DIRECTION INPUT ;
    USE SIGNAL ;
    SHAPE ABUTMENT ;
    PORT
      LAYER met2 ;
      RECT 129.650 0.000 129.790 0.420 ;
    END
  END rw0_wd_in[87]
  PIN rw0_wd_in[88]
    DIRECTION INPUT ;
    USE SIGNAL ;
    SHAPE ABUTMENT ;
    PORT
      LAYER met2 ;
      RECT 135.170 0.000 135.310 0.420 ;
    END
  END rw0_wd_in[88]
  PIN rw0_wd_in[89]
    DIRECTION INPUT ;
    USE SIGNAL ;
    SHAPE ABUTMENT ;
    PORT
      LAYER met2 ;
      RECT 140.690 0.000 140.830 0.420 ;
    END
  END rw0_wd_in[89]
  PIN rw0_wd_in[90]
    DIRECTION INPUT ;
    USE SIGNAL ;
    SHAPE ABUTMENT ;
    PORT
      LAYER met2 ;
      RECT 146.210 0.000 146.350 0.420 ;
    END
  END rw0_wd_in[90]
  PIN rw0_wd_in[91]
    DIRECTION INPUT ;
    USE SIGNAL ;
    SHAPE ABUTMENT ;
    PORT
      LAYER met2 ;
      RECT 151.730 0.000 151.870 0.420 ;
    END
  END rw0_wd_in[91]
  PIN rw0_wd_in[92]
    DIRECTION INPUT ;
    USE SIGNAL ;
    SHAPE ABUTMENT ;
    PORT
      LAYER met2 ;
      RECT 157.250 0.000 157.390 0.420 ;
    END
  END rw0_wd_in[92]
  PIN rw0_wd_in[93]
    DIRECTION INPUT ;
    USE SIGNAL ;
    SHAPE ABUTMENT ;
    PORT
      LAYER met2 ;
      RECT 162.770 0.000 162.910 0.420 ;
    END
  END rw0_wd_in[93]
  PIN rw0_wd_in[94]
    DIRECTION INPUT ;
    USE SIGNAL ;
    SHAPE ABUTMENT ;
    PORT
      LAYER met2 ;
      RECT 168.290 0.000 168.430 0.420 ;
    END
  END rw0_wd_in[94]
  PIN rw0_wd_in[95]
    DIRECTION INPUT ;
    USE SIGNAL ;
    SHAPE ABUTMENT ;
    PORT
      LAYER met2 ;
      RECT 173.810 0.000 173.950 0.420 ;
    END
  END rw0_wd_in[95]
  PIN rw0_wd_in[96]
    DIRECTION INPUT ;
    USE SIGNAL ;
    SHAPE ABUTMENT ;
    PORT
      LAYER met2 ;
      RECT 179.330 0.000 179.470 0.420 ;
    END
  END rw0_wd_in[96]
  PIN rw0_wd_in[97]
    DIRECTION INPUT ;
    USE SIGNAL ;
    SHAPE ABUTMENT ;
    PORT
      LAYER met2 ;
      RECT 184.850 0.000 184.990 0.420 ;
    END
  END rw0_wd_in[97]
  PIN rw0_wd_in[98]
    DIRECTION INPUT ;
    USE SIGNAL ;
    SHAPE ABUTMENT ;
    PORT
      LAYER met2 ;
      RECT 190.370 0.000 190.510 0.420 ;
    END
  END rw0_wd_in[98]
  PIN rw0_wd_in[99]
    DIRECTION INPUT ;
    USE SIGNAL ;
    SHAPE ABUTMENT ;
    PORT
      LAYER met2 ;
      RECT 195.890 0.000 196.030 0.420 ;
    END
  END rw0_wd_in[99]
  PIN rw0_wd_in[100]
    DIRECTION INPUT ;
    USE SIGNAL ;
    SHAPE ABUTMENT ;
    PORT
      LAYER met2 ;
      RECT 201.410 0.000 201.550 0.420 ;
    END
  END rw0_wd_in[100]
  PIN rw0_wd_in[101]
    DIRECTION INPUT ;
    USE SIGNAL ;
    SHAPE ABUTMENT ;
    PORT
      LAYER met2 ;
      RECT 206.930 0.000 207.070 0.420 ;
    END
  END rw0_wd_in[101]
  PIN rw0_wd_in[102]
    DIRECTION INPUT ;
    USE SIGNAL ;
    SHAPE ABUTMENT ;
    PORT
      LAYER met2 ;
      RECT 212.450 0.000 212.590 0.420 ;
    END
  END rw0_wd_in[102]
  PIN rw0_wd_in[103]
    DIRECTION INPUT ;
    USE SIGNAL ;
    SHAPE ABUTMENT ;
    PORT
      LAYER met2 ;
      RECT 217.970 0.000 218.110 0.420 ;
    END
  END rw0_wd_in[103]
  PIN rw0_wd_in[104]
    DIRECTION INPUT ;
    USE SIGNAL ;
    SHAPE ABUTMENT ;
    PORT
      LAYER met2 ;
      RECT 223.490 0.000 223.630 0.420 ;
    END
  END rw0_wd_in[104]
  PIN rw0_wd_in[105]
    DIRECTION INPUT ;
    USE SIGNAL ;
    SHAPE ABUTMENT ;
    PORT
      LAYER met2 ;
      RECT 229.010 0.000 229.150 0.420 ;
    END
  END rw0_wd_in[105]
  PIN rw0_wd_in[106]
    DIRECTION INPUT ;
    USE SIGNAL ;
    SHAPE ABUTMENT ;
    PORT
      LAYER met2 ;
      RECT 234.530 0.000 234.670 0.420 ;
    END
  END rw0_wd_in[106]
  PIN rw0_wd_in[107]
    DIRECTION INPUT ;
    USE SIGNAL ;
    SHAPE ABUTMENT ;
    PORT
      LAYER met2 ;
      RECT 240.050 0.000 240.190 0.420 ;
    END
  END rw0_wd_in[107]
  PIN rw0_wd_in[108]
    DIRECTION INPUT ;
    USE SIGNAL ;
    SHAPE ABUTMENT ;
    PORT
      LAYER met2 ;
      RECT 245.570 0.000 245.710 0.420 ;
    END
  END rw0_wd_in[108]
  PIN rw0_wd_in[109]
    DIRECTION INPUT ;
    USE SIGNAL ;
    SHAPE ABUTMENT ;
    PORT
      LAYER met2 ;
      RECT 251.090 0.000 251.230 0.420 ;
    END
  END rw0_wd_in[109]
  PIN rw0_wd_in[110]
    DIRECTION INPUT ;
    USE SIGNAL ;
    SHAPE ABUTMENT ;
    PORT
      LAYER met2 ;
      RECT 256.610 0.000 256.750 0.420 ;
    END
  END rw0_wd_in[110]
  PIN rw0_wd_in[111]
    DIRECTION INPUT ;
    USE SIGNAL ;
    SHAPE ABUTMENT ;
    PORT
      LAYER met2 ;
      RECT 262.130 0.000 262.270 0.420 ;
    END
  END rw0_wd_in[111]
  PIN rw0_wd_in[112]
    DIRECTION INPUT ;
    USE SIGNAL ;
    SHAPE ABUTMENT ;
    PORT
      LAYER met2 ;
      RECT 267.650 0.000 267.790 0.420 ;
    END
  END rw0_wd_in[112]
  PIN rw0_wd_in[113]
    DIRECTION INPUT ;
    USE SIGNAL ;
    SHAPE ABUTMENT ;
    PORT
      LAYER met2 ;
      RECT 273.170 0.000 273.310 0.420 ;
    END
  END rw0_wd_in[113]
  PIN rw0_wd_in[114]
    DIRECTION INPUT ;
    USE SIGNAL ;
    SHAPE ABUTMENT ;
    PORT
      LAYER met2 ;
      RECT 278.690 0.000 278.830 0.420 ;
    END
  END rw0_wd_in[114]
  PIN rw0_wd_in[115]
    DIRECTION INPUT ;
    USE SIGNAL ;
    SHAPE ABUTMENT ;
    PORT
      LAYER met2 ;
      RECT 284.210 0.000 284.350 0.420 ;
    END
  END rw0_wd_in[115]
  PIN rw0_wd_in[116]
    DIRECTION INPUT ;
    USE SIGNAL ;
    SHAPE ABUTMENT ;
    PORT
      LAYER met2 ;
      RECT 289.730 0.000 289.870 0.420 ;
    END
  END rw0_wd_in[116]
  PIN rw0_wd_in[117]
    DIRECTION INPUT ;
    USE SIGNAL ;
    SHAPE ABUTMENT ;
    PORT
      LAYER met2 ;
      RECT 295.250 0.000 295.390 0.420 ;
    END
  END rw0_wd_in[117]
  PIN rw0_wd_in[118]
    DIRECTION INPUT ;
    USE SIGNAL ;
    SHAPE ABUTMENT ;
    PORT
      LAYER met2 ;
      RECT 300.770 0.000 300.910 0.420 ;
    END
  END rw0_wd_in[118]
  PIN rw0_wd_in[119]
    DIRECTION INPUT ;
    USE SIGNAL ;
    SHAPE ABUTMENT ;
    PORT
      LAYER met2 ;
      RECT 306.290 0.000 306.430 0.420 ;
    END
  END rw0_wd_in[119]
  PIN rw0_wd_in[120]
    DIRECTION INPUT ;
    USE SIGNAL ;
    SHAPE ABUTMENT ;
    PORT
      LAYER met2 ;
      RECT 311.810 0.000 311.950 0.420 ;
    END
  END rw0_wd_in[120]
  PIN rw0_wd_in[121]
    DIRECTION INPUT ;
    USE SIGNAL ;
    SHAPE ABUTMENT ;
    PORT
      LAYER met2 ;
      RECT 317.330 0.000 317.470 0.420 ;
    END
  END rw0_wd_in[121]
  PIN rw0_wd_in[122]
    DIRECTION INPUT ;
    USE SIGNAL ;
    SHAPE ABUTMENT ;
    PORT
      LAYER met2 ;
      RECT 322.850 0.000 322.990 0.420 ;
    END
  END rw0_wd_in[122]
  PIN rw0_wd_in[123]
    DIRECTION INPUT ;
    USE SIGNAL ;
    SHAPE ABUTMENT ;
    PORT
      LAYER met2 ;
      RECT 328.370 0.000 328.510 0.420 ;
    END
  END rw0_wd_in[123]
  PIN rw0_wd_in[124]
    DIRECTION INPUT ;
    USE SIGNAL ;
    SHAPE ABUTMENT ;
    PORT
      LAYER met2 ;
      RECT 333.890 0.000 334.030 0.420 ;
    END
  END rw0_wd_in[124]
  PIN rw0_wd_in[125]
    DIRECTION INPUT ;
    USE SIGNAL ;
    SHAPE ABUTMENT ;
    PORT
      LAYER met2 ;
      RECT 339.410 0.000 339.550 0.420 ;
    END
  END rw0_wd_in[125]
  PIN rw0_wd_in[126]
    DIRECTION INPUT ;
    USE SIGNAL ;
    SHAPE ABUTMENT ;
    PORT
      LAYER met2 ;
      RECT 344.930 0.000 345.070 0.420 ;
    END
  END rw0_wd_in[126]
  PIN rw0_wd_in[127]
    DIRECTION INPUT ;
    USE SIGNAL ;
    SHAPE ABUTMENT ;
    PORT
      LAYER met2 ;
      RECT 350.450 0.000 350.590 0.420 ;
    END
  END rw0_wd_in[127]
  PIN rw0_rd_out[0]
    DIRECTION OUTPUT ;
    USE SIGNAL ;
    SHAPE ABUTMENT ;
    PORT
      LAYER met2 ;
      RECT 355.970 0.000 356.110 0.420 ;
    END
  END rw0_rd_out[0]
  PIN rw0_rd_out[1]
    DIRECTION OUTPUT ;
    USE SIGNAL ;
    SHAPE ABUTMENT ;
    PORT
      LAYER met2 ;
      RECT 361.490 0.000 361.630 0.420 ;
    END
  END rw0_rd_out[1]
  PIN rw0_rd_out[2]
    DIRECTION OUTPUT ;
    USE SIGNAL ;
    SHAPE ABUTMENT ;
    PORT
      LAYER met2 ;
      RECT 367.010 0.000 367.150 0.420 ;
    END
  END rw0_rd_out[2]
  PIN rw0_rd_out[3]
    DIRECTION OUTPUT ;
    USE SIGNAL ;
    SHAPE ABUTMENT ;
    PORT
      LAYER met2 ;
      RECT 372.530 0.000 372.670 0.420 ;
    END
  END rw0_rd_out[3]
  PIN rw0_rd_out[4]
    DIRECTION OUTPUT ;
    USE SIGNAL ;
    SHAPE ABUTMENT ;
    PORT
      LAYER met2 ;
      RECT 378.050 0.000 378.190 0.420 ;
    END
  END rw0_rd_out[4]
  PIN rw0_rd_out[5]
    DIRECTION OUTPUT ;
    USE SIGNAL ;
    SHAPE ABUTMENT ;
    PORT
      LAYER met2 ;
      RECT 383.570 0.000 383.710 0.420 ;
    END
  END rw0_rd_out[5]
  PIN rw0_rd_out[6]
    DIRECTION OUTPUT ;
    USE SIGNAL ;
    SHAPE ABUTMENT ;
    PORT
      LAYER met2 ;
      RECT 389.090 0.000 389.230 0.420 ;
    END
  END rw0_rd_out[6]
  PIN rw0_rd_out[7]
    DIRECTION OUTPUT ;
    USE SIGNAL ;
    SHAPE ABUTMENT ;
    PORT
      LAYER met2 ;
      RECT 394.610 0.000 394.750 0.420 ;
    END
  END rw0_rd_out[7]
  PIN rw0_rd_out[8]
    DIRECTION OUTPUT ;
    USE SIGNAL ;
    SHAPE ABUTMENT ;
    PORT
      LAYER met2 ;
      RECT 400.130 0.000 400.270 0.420 ;
    END
  END rw0_rd_out[8]
  PIN rw0_rd_out[9]
    DIRECTION OUTPUT ;
    USE SIGNAL ;
    SHAPE ABUTMENT ;
    PORT
      LAYER met2 ;
      RECT 405.650 0.000 405.790 0.420 ;
    END
  END rw0_rd_out[9]
  PIN rw0_rd_out[10]
    DIRECTION OUTPUT ;
    USE SIGNAL ;
    SHAPE ABUTMENT ;
    PORT
      LAYER met2 ;
      RECT 411.170 0.000 411.310 0.420 ;
    END
  END rw0_rd_out[10]
  PIN rw0_rd_out[11]
    DIRECTION OUTPUT ;
    USE SIGNAL ;
    SHAPE ABUTMENT ;
    PORT
      LAYER met2 ;
      RECT 416.690 0.000 416.830 0.420 ;
    END
  END rw0_rd_out[11]
  PIN rw0_rd_out[12]
    DIRECTION OUTPUT ;
    USE SIGNAL ;
    SHAPE ABUTMENT ;
    PORT
      LAYER met2 ;
      RECT 422.210 0.000 422.350 0.420 ;
    END
  END rw0_rd_out[12]
  PIN rw0_rd_out[13]
    DIRECTION OUTPUT ;
    USE SIGNAL ;
    SHAPE ABUTMENT ;
    PORT
      LAYER met2 ;
      RECT 427.730 0.000 427.870 0.420 ;
    END
  END rw0_rd_out[13]
  PIN rw0_rd_out[14]
    DIRECTION OUTPUT ;
    USE SIGNAL ;
    SHAPE ABUTMENT ;
    PORT
      LAYER met2 ;
      RECT 433.250 0.000 433.390 0.420 ;
    END
  END rw0_rd_out[14]
  PIN rw0_rd_out[15]
    DIRECTION OUTPUT ;
    USE SIGNAL ;
    SHAPE ABUTMENT ;
    PORT
      LAYER met2 ;
      RECT 438.770 0.000 438.910 0.420 ;
    END
  END rw0_rd_out[15]
  PIN rw0_rd_out[16]
    DIRECTION OUTPUT ;
    USE SIGNAL ;
    SHAPE ABUTMENT ;
    PORT
      LAYER met2 ;
      RECT 444.290 0.000 444.430 0.420 ;
    END
  END rw0_rd_out[16]
  PIN rw0_rd_out[17]
    DIRECTION OUTPUT ;
    USE SIGNAL ;
    SHAPE ABUTMENT ;
    PORT
      LAYER met2 ;
      RECT 449.810 0.000 449.950 0.420 ;
    END
  END rw0_rd_out[17]
  PIN rw0_rd_out[18]
    DIRECTION OUTPUT ;
    USE SIGNAL ;
    SHAPE ABUTMENT ;
    PORT
      LAYER met2 ;
      RECT 455.330 0.000 455.470 0.420 ;
    END
  END rw0_rd_out[18]
  PIN rw0_rd_out[19]
    DIRECTION OUTPUT ;
    USE SIGNAL ;
    SHAPE ABUTMENT ;
    PORT
      LAYER met2 ;
      RECT 460.850 0.000 460.990 0.420 ;
    END
  END rw0_rd_out[19]
  PIN rw0_rd_out[20]
    DIRECTION OUTPUT ;
    USE SIGNAL ;
    SHAPE ABUTMENT ;
    PORT
      LAYER met2 ;
      RECT 466.370 0.000 466.510 0.420 ;
    END
  END rw0_rd_out[20]
  PIN rw0_rd_out[21]
    DIRECTION OUTPUT ;
    USE SIGNAL ;
    SHAPE ABUTMENT ;
    PORT
      LAYER met2 ;
      RECT 471.890 0.000 472.030 0.420 ;
    END
  END rw0_rd_out[21]
  PIN rw0_rd_out[22]
    DIRECTION OUTPUT ;
    USE SIGNAL ;
    SHAPE ABUTMENT ;
    PORT
      LAYER met2 ;
      RECT 477.410 0.000 477.550 0.420 ;
    END
  END rw0_rd_out[22]
  PIN rw0_rd_out[23]
    DIRECTION OUTPUT ;
    USE SIGNAL ;
    SHAPE ABUTMENT ;
    PORT
      LAYER met2 ;
      RECT 482.930 0.000 483.070 0.420 ;
    END
  END rw0_rd_out[23]
  PIN rw0_rd_out[24]
    DIRECTION OUTPUT ;
    USE SIGNAL ;
    SHAPE ABUTMENT ;
    PORT
      LAYER met2 ;
      RECT 488.450 0.000 488.590 0.420 ;
    END
  END rw0_rd_out[24]
  PIN rw0_rd_out[25]
    DIRECTION OUTPUT ;
    USE SIGNAL ;
    SHAPE ABUTMENT ;
    PORT
      LAYER met2 ;
      RECT 493.970 0.000 494.110 0.420 ;
    END
  END rw0_rd_out[25]
  PIN rw0_rd_out[26]
    DIRECTION OUTPUT ;
    USE SIGNAL ;
    SHAPE ABUTMENT ;
    PORT
      LAYER met2 ;
      RECT 499.490 0.000 499.630 0.420 ;
    END
  END rw0_rd_out[26]
  PIN rw0_rd_out[27]
    DIRECTION OUTPUT ;
    USE SIGNAL ;
    SHAPE ABUTMENT ;
    PORT
      LAYER met2 ;
      RECT 505.010 0.000 505.150 0.420 ;
    END
  END rw0_rd_out[27]
  PIN rw0_rd_out[28]
    DIRECTION OUTPUT ;
    USE SIGNAL ;
    SHAPE ABUTMENT ;
    PORT
      LAYER met2 ;
      RECT 510.530 0.000 510.670 0.420 ;
    END
  END rw0_rd_out[28]
  PIN rw0_rd_out[29]
    DIRECTION OUTPUT ;
    USE SIGNAL ;
    SHAPE ABUTMENT ;
    PORT
      LAYER met2 ;
      RECT 516.050 0.000 516.190 0.420 ;
    END
  END rw0_rd_out[29]
  PIN rw0_rd_out[30]
    DIRECTION OUTPUT ;
    USE SIGNAL ;
    SHAPE ABUTMENT ;
    PORT
      LAYER met2 ;
      RECT 521.570 0.000 521.710 0.420 ;
    END
  END rw0_rd_out[30]
  PIN rw0_rd_out[31]
    DIRECTION OUTPUT ;
    USE SIGNAL ;
    SHAPE ABUTMENT ;
    PORT
      LAYER met2 ;
      RECT 527.090 0.000 527.230 0.420 ;
    END
  END rw0_rd_out[31]
  PIN rw0_rd_out[32]
    DIRECTION OUTPUT ;
    USE SIGNAL ;
    SHAPE ABUTMENT ;
    PORT
      LAYER met2 ;
      RECT 532.610 0.000 532.750 0.420 ;
    END
  END rw0_rd_out[32]
  PIN rw0_rd_out[33]
    DIRECTION OUTPUT ;
    USE SIGNAL ;
    SHAPE ABUTMENT ;
    PORT
      LAYER met2 ;
      RECT 538.130 0.000 538.270 0.420 ;
    END
  END rw0_rd_out[33]
  PIN rw0_rd_out[34]
    DIRECTION OUTPUT ;
    USE SIGNAL ;
    SHAPE ABUTMENT ;
    PORT
      LAYER met2 ;
      RECT 543.650 0.000 543.790 0.420 ;
    END
  END rw0_rd_out[34]
  PIN rw0_rd_out[35]
    DIRECTION OUTPUT ;
    USE SIGNAL ;
    SHAPE ABUTMENT ;
    PORT
      LAYER met2 ;
      RECT 549.170 0.000 549.310 0.420 ;
    END
  END rw0_rd_out[35]
  PIN rw0_rd_out[36]
    DIRECTION OUTPUT ;
    USE SIGNAL ;
    SHAPE ABUTMENT ;
    PORT
      LAYER met2 ;
      RECT 554.690 0.000 554.830 0.420 ;
    END
  END rw0_rd_out[36]
  PIN rw0_rd_out[37]
    DIRECTION OUTPUT ;
    USE SIGNAL ;
    SHAPE ABUTMENT ;
    PORT
      LAYER met2 ;
      RECT 560.210 0.000 560.350 0.420 ;
    END
  END rw0_rd_out[37]
  PIN rw0_rd_out[38]
    DIRECTION OUTPUT ;
    USE SIGNAL ;
    SHAPE ABUTMENT ;
    PORT
      LAYER met2 ;
      RECT 565.730 0.000 565.870 0.420 ;
    END
  END rw0_rd_out[38]
  PIN rw0_rd_out[39]
    DIRECTION OUTPUT ;
    USE SIGNAL ;
    SHAPE ABUTMENT ;
    PORT
      LAYER met2 ;
      RECT 571.250 0.000 571.390 0.420 ;
    END
  END rw0_rd_out[39]
  PIN rw0_rd_out[40]
    DIRECTION OUTPUT ;
    USE SIGNAL ;
    SHAPE ABUTMENT ;
    PORT
      LAYER met2 ;
      RECT 576.770 0.000 576.910 0.420 ;
    END
  END rw0_rd_out[40]
  PIN rw0_rd_out[41]
    DIRECTION OUTPUT ;
    USE SIGNAL ;
    SHAPE ABUTMENT ;
    PORT
      LAYER met2 ;
      RECT 582.290 0.000 582.430 0.420 ;
    END
  END rw0_rd_out[41]
  PIN rw0_rd_out[42]
    DIRECTION OUTPUT ;
    USE SIGNAL ;
    SHAPE ABUTMENT ;
    PORT
      LAYER met2 ;
      RECT 587.810 0.000 587.950 0.420 ;
    END
  END rw0_rd_out[42]
  PIN rw0_rd_out[43]
    DIRECTION OUTPUT ;
    USE SIGNAL ;
    SHAPE ABUTMENT ;
    PORT
      LAYER met2 ;
      RECT 593.330 0.000 593.470 0.420 ;
    END
  END rw0_rd_out[43]
  PIN rw0_rd_out[44]
    DIRECTION OUTPUT ;
    USE SIGNAL ;
    SHAPE ABUTMENT ;
    PORT
      LAYER met2 ;
      RECT 598.850 0.000 598.990 0.420 ;
    END
  END rw0_rd_out[44]
  PIN rw0_rd_out[45]
    DIRECTION OUTPUT ;
    USE SIGNAL ;
    SHAPE ABUTMENT ;
    PORT
      LAYER met2 ;
      RECT 604.370 0.000 604.510 0.420 ;
    END
  END rw0_rd_out[45]
  PIN rw0_rd_out[46]
    DIRECTION OUTPUT ;
    USE SIGNAL ;
    SHAPE ABUTMENT ;
    PORT
      LAYER met2 ;
      RECT 609.890 0.000 610.030 0.420 ;
    END
  END rw0_rd_out[46]
  PIN rw0_rd_out[47]
    DIRECTION OUTPUT ;
    USE SIGNAL ;
    SHAPE ABUTMENT ;
    PORT
      LAYER met2 ;
      RECT 615.410 0.000 615.550 0.420 ;
    END
  END rw0_rd_out[47]
  PIN rw0_rd_out[48]
    DIRECTION OUTPUT ;
    USE SIGNAL ;
    SHAPE ABUTMENT ;
    PORT
      LAYER met2 ;
      RECT 620.930 0.000 621.070 0.420 ;
    END
  END rw0_rd_out[48]
  PIN rw0_rd_out[49]
    DIRECTION OUTPUT ;
    USE SIGNAL ;
    SHAPE ABUTMENT ;
    PORT
      LAYER met2 ;
      RECT 626.450 0.000 626.590 0.420 ;
    END
  END rw0_rd_out[49]
  PIN rw0_rd_out[50]
    DIRECTION OUTPUT ;
    USE SIGNAL ;
    SHAPE ABUTMENT ;
    PORT
      LAYER met2 ;
      RECT 631.970 0.000 632.110 0.420 ;
    END
  END rw0_rd_out[50]
  PIN rw0_rd_out[51]
    DIRECTION OUTPUT ;
    USE SIGNAL ;
    SHAPE ABUTMENT ;
    PORT
      LAYER met2 ;
      RECT 637.490 0.000 637.630 0.420 ;
    END
  END rw0_rd_out[51]
  PIN rw0_rd_out[52]
    DIRECTION OUTPUT ;
    USE SIGNAL ;
    SHAPE ABUTMENT ;
    PORT
      LAYER met2 ;
      RECT 643.010 0.000 643.150 0.420 ;
    END
  END rw0_rd_out[52]
  PIN rw0_rd_out[53]
    DIRECTION OUTPUT ;
    USE SIGNAL ;
    SHAPE ABUTMENT ;
    PORT
      LAYER met2 ;
      RECT 648.530 0.000 648.670 0.420 ;
    END
  END rw0_rd_out[53]
  PIN rw0_rd_out[54]
    DIRECTION OUTPUT ;
    USE SIGNAL ;
    SHAPE ABUTMENT ;
    PORT
      LAYER met2 ;
      RECT 654.050 0.000 654.190 0.420 ;
    END
  END rw0_rd_out[54]
  PIN rw0_rd_out[55]
    DIRECTION OUTPUT ;
    USE SIGNAL ;
    SHAPE ABUTMENT ;
    PORT
      LAYER met2 ;
      RECT 659.570 0.000 659.710 0.420 ;
    END
  END rw0_rd_out[55]
  PIN rw0_rd_out[56]
    DIRECTION OUTPUT ;
    USE SIGNAL ;
    SHAPE ABUTMENT ;
    PORT
      LAYER met2 ;
      RECT 665.090 0.000 665.230 0.420 ;
    END
  END rw0_rd_out[56]
  PIN rw0_rd_out[57]
    DIRECTION OUTPUT ;
    USE SIGNAL ;
    SHAPE ABUTMENT ;
    PORT
      LAYER met2 ;
      RECT 670.610 0.000 670.750 0.420 ;
    END
  END rw0_rd_out[57]
  PIN rw0_rd_out[58]
    DIRECTION OUTPUT ;
    USE SIGNAL ;
    SHAPE ABUTMENT ;
    PORT
      LAYER met2 ;
      RECT 676.130 0.000 676.270 0.420 ;
    END
  END rw0_rd_out[58]
  PIN rw0_rd_out[59]
    DIRECTION OUTPUT ;
    USE SIGNAL ;
    SHAPE ABUTMENT ;
    PORT
      LAYER met2 ;
      RECT 681.650 0.000 681.790 0.420 ;
    END
  END rw0_rd_out[59]
  PIN rw0_rd_out[60]
    DIRECTION OUTPUT ;
    USE SIGNAL ;
    SHAPE ABUTMENT ;
    PORT
      LAYER met2 ;
      RECT 687.170 0.000 687.310 0.420 ;
    END
  END rw0_rd_out[60]
  PIN rw0_rd_out[61]
    DIRECTION OUTPUT ;
    USE SIGNAL ;
    SHAPE ABUTMENT ;
    PORT
      LAYER met2 ;
      RECT 692.690 0.000 692.830 0.420 ;
    END
  END rw0_rd_out[61]
  PIN rw0_rd_out[62]
    DIRECTION OUTPUT ;
    USE SIGNAL ;
    SHAPE ABUTMENT ;
    PORT
      LAYER met2 ;
      RECT 698.210 0.000 698.350 0.420 ;
    END
  END rw0_rd_out[62]
  PIN rw0_rd_out[63]
    DIRECTION OUTPUT ;
    USE SIGNAL ;
    SHAPE ABUTMENT ;
    PORT
      LAYER met2 ;
      RECT 703.730 0.000 703.870 0.420 ;
    END
  END rw0_rd_out[63]
  PIN rw0_rd_out[64]
    DIRECTION OUTPUT ;
    USE SIGNAL ;
    SHAPE ABUTMENT ;
    PORT
      LAYER met2 ;
      RECT 326.530 581.660 326.670 582.080 ;
    END
  END rw0_rd_out[64]
  PIN rw0_rd_out[65]
    DIRECTION OUTPUT ;
    USE SIGNAL ;
    SHAPE ABUTMENT ;
    PORT
      LAYER met2 ;
      RECT 331.590 581.660 331.730 582.080 ;
    END
  END rw0_rd_out[65]
  PIN rw0_rd_out[66]
    DIRECTION OUTPUT ;
    USE SIGNAL ;
    SHAPE ABUTMENT ;
    PORT
      LAYER met2 ;
      RECT 336.650 581.660 336.790 582.080 ;
    END
  END rw0_rd_out[66]
  PIN rw0_rd_out[67]
    DIRECTION OUTPUT ;
    USE SIGNAL ;
    SHAPE ABUTMENT ;
    PORT
      LAYER met2 ;
      RECT 341.710 581.660 341.850 582.080 ;
    END
  END rw0_rd_out[67]
  PIN rw0_rd_out[68]
    DIRECTION OUTPUT ;
    USE SIGNAL ;
    SHAPE ABUTMENT ;
    PORT
      LAYER met2 ;
      RECT 346.770 581.660 346.910 582.080 ;
    END
  END rw0_rd_out[68]
  PIN rw0_rd_out[69]
    DIRECTION OUTPUT ;
    USE SIGNAL ;
    SHAPE ABUTMENT ;
    PORT
      LAYER met2 ;
      RECT 351.830 581.660 351.970 582.080 ;
    END
  END rw0_rd_out[69]
  PIN rw0_rd_out[70]
    DIRECTION OUTPUT ;
    USE SIGNAL ;
    SHAPE ABUTMENT ;
    PORT
      LAYER met2 ;
      RECT 356.890 581.660 357.030 582.080 ;
    END
  END rw0_rd_out[70]
  PIN rw0_rd_out[71]
    DIRECTION OUTPUT ;
    USE SIGNAL ;
    SHAPE ABUTMENT ;
    PORT
      LAYER met2 ;
      RECT 361.950 581.660 362.090 582.080 ;
    END
  END rw0_rd_out[71]
  PIN rw0_rd_out[72]
    DIRECTION OUTPUT ;
    USE SIGNAL ;
    SHAPE ABUTMENT ;
    PORT
      LAYER met2 ;
      RECT 367.010 581.660 367.150 582.080 ;
    END
  END rw0_rd_out[72]
  PIN rw0_rd_out[73]
    DIRECTION OUTPUT ;
    USE SIGNAL ;
    SHAPE ABUTMENT ;
    PORT
      LAYER met2 ;
      RECT 372.070 581.660 372.210 582.080 ;
    END
  END rw0_rd_out[73]
  PIN rw0_rd_out[74]
    DIRECTION OUTPUT ;
    USE SIGNAL ;
    SHAPE ABUTMENT ;
    PORT
      LAYER met2 ;
      RECT 377.130 581.660 377.270 582.080 ;
    END
  END rw0_rd_out[74]
  PIN rw0_rd_out[75]
    DIRECTION OUTPUT ;
    USE SIGNAL ;
    SHAPE ABUTMENT ;
    PORT
      LAYER met2 ;
      RECT 382.190 581.660 382.330 582.080 ;
    END
  END rw0_rd_out[75]
  PIN rw0_rd_out[76]
    DIRECTION OUTPUT ;
    USE SIGNAL ;
    SHAPE ABUTMENT ;
    PORT
      LAYER met2 ;
      RECT 387.250 581.660 387.390 582.080 ;
    END
  END rw0_rd_out[76]
  PIN rw0_rd_out[77]
    DIRECTION OUTPUT ;
    USE SIGNAL ;
    SHAPE ABUTMENT ;
    PORT
      LAYER met2 ;
      RECT 392.310 581.660 392.450 582.080 ;
    END
  END rw0_rd_out[77]
  PIN rw0_rd_out[78]
    DIRECTION OUTPUT ;
    USE SIGNAL ;
    SHAPE ABUTMENT ;
    PORT
      LAYER met2 ;
      RECT 397.370 581.660 397.510 582.080 ;
    END
  END rw0_rd_out[78]
  PIN rw0_rd_out[79]
    DIRECTION OUTPUT ;
    USE SIGNAL ;
    SHAPE ABUTMENT ;
    PORT
      LAYER met2 ;
      RECT 402.430 581.660 402.570 582.080 ;
    END
  END rw0_rd_out[79]
  PIN rw0_rd_out[80]
    DIRECTION OUTPUT ;
    USE SIGNAL ;
    SHAPE ABUTMENT ;
    PORT
      LAYER met2 ;
      RECT 407.490 581.660 407.630 582.080 ;
    END
  END rw0_rd_out[80]
  PIN rw0_rd_out[81]
    DIRECTION OUTPUT ;
    USE SIGNAL ;
    SHAPE ABUTMENT ;
    PORT
      LAYER met2 ;
      RECT 412.550 581.660 412.690 582.080 ;
    END
  END rw0_rd_out[81]
  PIN rw0_rd_out[82]
    DIRECTION OUTPUT ;
    USE SIGNAL ;
    SHAPE ABUTMENT ;
    PORT
      LAYER met2 ;
      RECT 417.610 581.660 417.750 582.080 ;
    END
  END rw0_rd_out[82]
  PIN rw0_rd_out[83]
    DIRECTION OUTPUT ;
    USE SIGNAL ;
    SHAPE ABUTMENT ;
    PORT
      LAYER met2 ;
      RECT 422.670 581.660 422.810 582.080 ;
    END
  END rw0_rd_out[83]
  PIN rw0_rd_out[84]
    DIRECTION OUTPUT ;
    USE SIGNAL ;
    SHAPE ABUTMENT ;
    PORT
      LAYER met2 ;
      RECT 427.730 581.660 427.870 582.080 ;
    END
  END rw0_rd_out[84]
  PIN rw0_rd_out[85]
    DIRECTION OUTPUT ;
    USE SIGNAL ;
    SHAPE ABUTMENT ;
    PORT
      LAYER met2 ;
      RECT 432.790 581.660 432.930 582.080 ;
    END
  END rw0_rd_out[85]
  PIN rw0_rd_out[86]
    DIRECTION OUTPUT ;
    USE SIGNAL ;
    SHAPE ABUTMENT ;
    PORT
      LAYER met2 ;
      RECT 437.850 581.660 437.990 582.080 ;
    END
  END rw0_rd_out[86]
  PIN rw0_rd_out[87]
    DIRECTION OUTPUT ;
    USE SIGNAL ;
    SHAPE ABUTMENT ;
    PORT
      LAYER met2 ;
      RECT 442.910 581.660 443.050 582.080 ;
    END
  END rw0_rd_out[87]
  PIN rw0_rd_out[88]
    DIRECTION OUTPUT ;
    USE SIGNAL ;
    SHAPE ABUTMENT ;
    PORT
      LAYER met2 ;
      RECT 447.970 581.660 448.110 582.080 ;
    END
  END rw0_rd_out[88]
  PIN rw0_rd_out[89]
    DIRECTION OUTPUT ;
    USE SIGNAL ;
    SHAPE ABUTMENT ;
    PORT
      LAYER met2 ;
      RECT 453.030 581.660 453.170 582.080 ;
    END
  END rw0_rd_out[89]
  PIN rw0_rd_out[90]
    DIRECTION OUTPUT ;
    USE SIGNAL ;
    SHAPE ABUTMENT ;
    PORT
      LAYER met2 ;
      RECT 458.090 581.660 458.230 582.080 ;
    END
  END rw0_rd_out[90]
  PIN rw0_rd_out[91]
    DIRECTION OUTPUT ;
    USE SIGNAL ;
    SHAPE ABUTMENT ;
    PORT
      LAYER met2 ;
      RECT 463.150 581.660 463.290 582.080 ;
    END
  END rw0_rd_out[91]
  PIN rw0_rd_out[92]
    DIRECTION OUTPUT ;
    USE SIGNAL ;
    SHAPE ABUTMENT ;
    PORT
      LAYER met2 ;
      RECT 468.210 581.660 468.350 582.080 ;
    END
  END rw0_rd_out[92]
  PIN rw0_rd_out[93]
    DIRECTION OUTPUT ;
    USE SIGNAL ;
    SHAPE ABUTMENT ;
    PORT
      LAYER met2 ;
      RECT 473.270 581.660 473.410 582.080 ;
    END
  END rw0_rd_out[93]
  PIN rw0_rd_out[94]
    DIRECTION OUTPUT ;
    USE SIGNAL ;
    SHAPE ABUTMENT ;
    PORT
      LAYER met2 ;
      RECT 478.330 581.660 478.470 582.080 ;
    END
  END rw0_rd_out[94]
  PIN rw0_rd_out[95]
    DIRECTION OUTPUT ;
    USE SIGNAL ;
    SHAPE ABUTMENT ;
    PORT
      LAYER met2 ;
      RECT 483.390 581.660 483.530 582.080 ;
    END
  END rw0_rd_out[95]
  PIN rw0_rd_out[96]
    DIRECTION OUTPUT ;
    USE SIGNAL ;
    SHAPE ABUTMENT ;
    PORT
      LAYER met2 ;
      RECT 488.450 581.660 488.590 582.080 ;
    END
  END rw0_rd_out[96]
  PIN rw0_rd_out[97]
    DIRECTION OUTPUT ;
    USE SIGNAL ;
    SHAPE ABUTMENT ;
    PORT
      LAYER met2 ;
      RECT 493.510 581.660 493.650 582.080 ;
    END
  END rw0_rd_out[97]
  PIN rw0_rd_out[98]
    DIRECTION OUTPUT ;
    USE SIGNAL ;
    SHAPE ABUTMENT ;
    PORT
      LAYER met2 ;
      RECT 498.570 581.660 498.710 582.080 ;
    END
  END rw0_rd_out[98]
  PIN rw0_rd_out[99]
    DIRECTION OUTPUT ;
    USE SIGNAL ;
    SHAPE ABUTMENT ;
    PORT
      LAYER met2 ;
      RECT 503.630 581.660 503.770 582.080 ;
    END
  END rw0_rd_out[99]
  PIN rw0_rd_out[100]
    DIRECTION OUTPUT ;
    USE SIGNAL ;
    SHAPE ABUTMENT ;
    PORT
      LAYER met2 ;
      RECT 508.690 581.660 508.830 582.080 ;
    END
  END rw0_rd_out[100]
  PIN rw0_rd_out[101]
    DIRECTION OUTPUT ;
    USE SIGNAL ;
    SHAPE ABUTMENT ;
    PORT
      LAYER met2 ;
      RECT 513.750 581.660 513.890 582.080 ;
    END
  END rw0_rd_out[101]
  PIN rw0_rd_out[102]
    DIRECTION OUTPUT ;
    USE SIGNAL ;
    SHAPE ABUTMENT ;
    PORT
      LAYER met2 ;
      RECT 518.810 581.660 518.950 582.080 ;
    END
  END rw0_rd_out[102]
  PIN rw0_rd_out[103]
    DIRECTION OUTPUT ;
    USE SIGNAL ;
    SHAPE ABUTMENT ;
    PORT
      LAYER met2 ;
      RECT 523.870 581.660 524.010 582.080 ;
    END
  END rw0_rd_out[103]
  PIN rw0_rd_out[104]
    DIRECTION OUTPUT ;
    USE SIGNAL ;
    SHAPE ABUTMENT ;
    PORT
      LAYER met2 ;
      RECT 528.930 581.660 529.070 582.080 ;
    END
  END rw0_rd_out[104]
  PIN rw0_rd_out[105]
    DIRECTION OUTPUT ;
    USE SIGNAL ;
    SHAPE ABUTMENT ;
    PORT
      LAYER met2 ;
      RECT 533.990 581.660 534.130 582.080 ;
    END
  END rw0_rd_out[105]
  PIN rw0_rd_out[106]
    DIRECTION OUTPUT ;
    USE SIGNAL ;
    SHAPE ABUTMENT ;
    PORT
      LAYER met2 ;
      RECT 539.050 581.660 539.190 582.080 ;
    END
  END rw0_rd_out[106]
  PIN rw0_rd_out[107]
    DIRECTION OUTPUT ;
    USE SIGNAL ;
    SHAPE ABUTMENT ;
    PORT
      LAYER met2 ;
      RECT 544.110 581.660 544.250 582.080 ;
    END
  END rw0_rd_out[107]
  PIN rw0_rd_out[108]
    DIRECTION OUTPUT ;
    USE SIGNAL ;
    SHAPE ABUTMENT ;
    PORT
      LAYER met2 ;
      RECT 549.170 581.660 549.310 582.080 ;
    END
  END rw0_rd_out[108]
  PIN rw0_rd_out[109]
    DIRECTION OUTPUT ;
    USE SIGNAL ;
    SHAPE ABUTMENT ;
    PORT
      LAYER met2 ;
      RECT 554.230 581.660 554.370 582.080 ;
    END
  END rw0_rd_out[109]
  PIN rw0_rd_out[110]
    DIRECTION OUTPUT ;
    USE SIGNAL ;
    SHAPE ABUTMENT ;
    PORT
      LAYER met2 ;
      RECT 559.290 581.660 559.430 582.080 ;
    END
  END rw0_rd_out[110]
  PIN rw0_rd_out[111]
    DIRECTION OUTPUT ;
    USE SIGNAL ;
    SHAPE ABUTMENT ;
    PORT
      LAYER met2 ;
      RECT 564.350 581.660 564.490 582.080 ;
    END
  END rw0_rd_out[111]
  PIN rw0_rd_out[112]
    DIRECTION OUTPUT ;
    USE SIGNAL ;
    SHAPE ABUTMENT ;
    PORT
      LAYER met2 ;
      RECT 569.410 581.660 569.550 582.080 ;
    END
  END rw0_rd_out[112]
  PIN rw0_rd_out[113]
    DIRECTION OUTPUT ;
    USE SIGNAL ;
    SHAPE ABUTMENT ;
    PORT
      LAYER met2 ;
      RECT 574.470 581.660 574.610 582.080 ;
    END
  END rw0_rd_out[113]
  PIN rw0_rd_out[114]
    DIRECTION OUTPUT ;
    USE SIGNAL ;
    SHAPE ABUTMENT ;
    PORT
      LAYER met2 ;
      RECT 579.530 581.660 579.670 582.080 ;
    END
  END rw0_rd_out[114]
  PIN rw0_rd_out[115]
    DIRECTION OUTPUT ;
    USE SIGNAL ;
    SHAPE ABUTMENT ;
    PORT
      LAYER met2 ;
      RECT 584.590 581.660 584.730 582.080 ;
    END
  END rw0_rd_out[115]
  PIN rw0_rd_out[116]
    DIRECTION OUTPUT ;
    USE SIGNAL ;
    SHAPE ABUTMENT ;
    PORT
      LAYER met2 ;
      RECT 589.650 581.660 589.790 582.080 ;
    END
  END rw0_rd_out[116]
  PIN rw0_rd_out[117]
    DIRECTION OUTPUT ;
    USE SIGNAL ;
    SHAPE ABUTMENT ;
    PORT
      LAYER met2 ;
      RECT 594.710 581.660 594.850 582.080 ;
    END
  END rw0_rd_out[117]
  PIN rw0_rd_out[118]
    DIRECTION OUTPUT ;
    USE SIGNAL ;
    SHAPE ABUTMENT ;
    PORT
      LAYER met2 ;
      RECT 599.770 581.660 599.910 582.080 ;
    END
  END rw0_rd_out[118]
  PIN rw0_rd_out[119]
    DIRECTION OUTPUT ;
    USE SIGNAL ;
    SHAPE ABUTMENT ;
    PORT
      LAYER met2 ;
      RECT 604.830 581.660 604.970 582.080 ;
    END
  END rw0_rd_out[119]
  PIN rw0_rd_out[120]
    DIRECTION OUTPUT ;
    USE SIGNAL ;
    SHAPE ABUTMENT ;
    PORT
      LAYER met2 ;
      RECT 609.890 581.660 610.030 582.080 ;
    END
  END rw0_rd_out[120]
  PIN rw0_rd_out[121]
    DIRECTION OUTPUT ;
    USE SIGNAL ;
    SHAPE ABUTMENT ;
    PORT
      LAYER met2 ;
      RECT 614.950 581.660 615.090 582.080 ;
    END
  END rw0_rd_out[121]
  PIN rw0_rd_out[122]
    DIRECTION OUTPUT ;
    USE SIGNAL ;
    SHAPE ABUTMENT ;
    PORT
      LAYER met2 ;
      RECT 620.010 581.660 620.150 582.080 ;
    END
  END rw0_rd_out[122]
  PIN rw0_rd_out[123]
    DIRECTION OUTPUT ;
    USE SIGNAL ;
    SHAPE ABUTMENT ;
    PORT
      LAYER met2 ;
      RECT 625.070 581.660 625.210 582.080 ;
    END
  END rw0_rd_out[123]
  PIN rw0_rd_out[124]
    DIRECTION OUTPUT ;
    USE SIGNAL ;
    SHAPE ABUTMENT ;
    PORT
      LAYER met2 ;
      RECT 630.130 581.660 630.270 582.080 ;
    END
  END rw0_rd_out[124]
  PIN rw0_rd_out[125]
    DIRECTION OUTPUT ;
    USE SIGNAL ;
    SHAPE ABUTMENT ;
    PORT
      LAYER met2 ;
      RECT 635.190 581.660 635.330 582.080 ;
    END
  END rw0_rd_out[125]
  PIN rw0_rd_out[126]
    DIRECTION OUTPUT ;
    USE SIGNAL ;
    SHAPE ABUTMENT ;
    PORT
      LAYER met2 ;
      RECT 640.250 581.660 640.390 582.080 ;
    END
  END rw0_rd_out[126]
  PIN rw0_rd_out[127]
    DIRECTION OUTPUT ;
    USE SIGNAL ;
    SHAPE ABUTMENT ;
    PORT
      LAYER met2 ;
      RECT 645.310 581.660 645.450 582.080 ;
    END
  END rw0_rd_out[127]
  PIN rw0_addr_in[0]
    DIRECTION INPUT ;
    USE SIGNAL ;
    SHAPE ABUTMENT ;
    PORT
      LAYER met3 ;
      RECT 0.000 526.170 0.900 526.470 ;
    END
  END rw0_addr_in[0]
  PIN rw0_addr_in[1]
    DIRECTION INPUT ;
    USE SIGNAL ;
    SHAPE ABUTMENT ;
    PORT
      LAYER met3 ;
      RECT 0.000 534.330 0.900 534.630 ;
    END
  END rw0_addr_in[1]
  PIN rw0_addr_in[2]
    DIRECTION INPUT ;
    USE SIGNAL ;
    SHAPE ABUTMENT ;
    PORT
      LAYER met3 ;
      RECT 0.000 542.490 0.900 542.790 ;
    END
  END rw0_addr_in[2]
  PIN rw0_addr_in[3]
    DIRECTION INPUT ;
    USE SIGNAL ;
    SHAPE ABUTMENT ;
    PORT
      LAYER met3 ;
      RECT 0.000 550.650 0.900 550.950 ;
    END
  END rw0_addr_in[3]
  PIN rw0_addr_in[4]
    DIRECTION INPUT ;
    USE SIGNAL ;
    SHAPE ABUTMENT ;
    PORT
      LAYER met3 ;
      RECT 714.860 526.170 715.760 526.470 ;
    END
  END rw0_addr_in[4]
  PIN rw0_addr_in[5]
    DIRECTION INPUT ;
    USE SIGNAL ;
    SHAPE ABUTMENT ;
    PORT
      LAYER met3 ;
      RECT 714.860 534.330 715.760 534.630 ;
    END
  END rw0_addr_in[5]
  PIN rw0_addr_in[6]
    DIRECTION INPUT ;
    USE SIGNAL ;
    SHAPE ABUTMENT ;
    PORT
      LAYER met3 ;
      RECT 714.860 542.490 715.760 542.790 ;
    END
  END rw0_addr_in[6]
  PIN rw0_addr_in[7]
    DIRECTION INPUT ;
    USE SIGNAL ;
    SHAPE ABUTMENT ;
    PORT
      LAYER met3 ;
      RECT 714.860 550.650 715.760 550.950 ;
    END
  END rw0_addr_in[7]
  PIN rw0_we_in
    DIRECTION INPUT ;
    USE SIGNAL ;
    SHAPE ABUTMENT ;
    PORT
      LAYER met2 ;
      RECT 650.370 581.660 650.510 582.080 ;
    END
  END rw0_we_in
  PIN rw0_ce_in
    DIRECTION INPUT ;
    USE SIGNAL ;
    SHAPE ABUTMENT ;
    PORT
      LAYER met2 ;
      RECT 655.430 581.660 655.570 582.080 ;
    END
  END rw0_ce_in
  PIN rw0_clk
    DIRECTION INPUT ;
    USE SIGNAL ;
    SHAPE ABUTMENT ;
    PORT
      LAYER met2 ;
      RECT 660.490 581.660 660.630 582.080 ;
    END
  END rw0_clk
  PIN VSS
    DIRECTION INOUT ;
    USE GROUND ;
    PORT
      LAYER met4 ;
      RECT 2.160 4.080 3.360 578.000 ;
      RECT 13.040 4.080 14.240 578.000 ;
      RECT 23.920 4.080 25.120 578.000 ;
      RECT 34.800 4.080 36.000 578.000 ;
      RECT 45.680 4.080 46.880 578.000 ;
      RECT 56.560 4.080 57.760 578.000 ;
      RECT 67.440 4.080 68.640 578.000 ;
      RECT 78.320 4.080 79.520 578.000 ;
      RECT 89.200 4.080 90.400 578.000 ;
      RECT 100.080 4.080 101.280 578.000 ;
      RECT 110.960 4.080 112.160 578.000 ;
      RECT 121.840 4.080 123.040 578.000 ;
      RECT 132.720 4.080 133.920 578.000 ;
      RECT 143.600 4.080 144.800 578.000 ;
      RECT 154.480 4.080 155.680 578.000 ;
      RECT 165.360 4.080 166.560 578.000 ;
      RECT 176.240 4.080 177.440 578.000 ;
      RECT 187.120 4.080 188.320 578.000 ;
      RECT 198.000 4.080 199.200 578.000 ;
      RECT 208.880 4.080 210.080 578.000 ;
      RECT 219.760 4.080 220.960 578.000 ;
      RECT 230.640 4.080 231.840 578.000 ;
      RECT 241.520 4.080 242.720 578.000 ;
      RECT 252.400 4.080 253.600 578.000 ;
      RECT 263.280 4.080 264.480 578.000 ;
      RECT 274.160 4.080 275.360 578.000 ;
      RECT 285.040 4.080 286.240 578.000 ;
      RECT 295.920 4.080 297.120 578.000 ;
      RECT 306.800 4.080 308.000 578.000 ;
      RECT 317.680 4.080 318.880 578.000 ;
      RECT 328.560 4.080 329.760 578.000 ;
      RECT 339.440 4.080 340.640 578.000 ;
      RECT 350.320 4.080 351.520 578.000 ;
      RECT 361.200 4.080 362.400 578.000 ;
      RECT 372.080 4.080 373.280 578.000 ;
      RECT 382.960 4.080 384.160 578.000 ;
      RECT 393.840 4.080 395.040 578.000 ;
      RECT 404.720 4.080 405.920 578.000 ;
      RECT 415.600 4.080 416.800 578.000 ;
      RECT 426.480 4.080 427.680 578.000 ;
      RECT 437.360 4.080 438.560 578.000 ;
      RECT 448.240 4.080 449.440 578.000 ;
      RECT 459.120 4.080 460.320 578.000 ;
      RECT 470.000 4.080 471.200 578.000 ;
      RECT 480.880 4.080 482.080 578.000 ;
      RECT 491.760 4.080 492.960 578.000 ;
      RECT 502.640 4.080 503.840 578.000 ;
      RECT 513.520 4.080 514.720 578.000 ;
      RECT 524.400 4.080 525.600 578.000 ;
      RECT 535.280 4.080 536.480 578.000 ;
      RECT 546.160 4.080 547.360 578.000 ;
      RECT 557.040 4.080 558.240 578.000 ;
      RECT 567.920 4.080 569.120 578.000 ;
      RECT 578.800 4.080 580.000 578.000 ;
      RECT 589.680 4.080 590.880 578.000 ;
      RECT 600.560 4.080 601.760 578.000 ;
      RECT 611.440 4.080 612.640 578.000 ;
      RECT 622.320 4.080 623.520 578.000 ;
      RECT 633.200 4.080 634.400 578.000 ;
      RECT 644.080 4.080 645.280 578.000 ;
      RECT 654.960 4.080 656.160 578.000 ;
      RECT 665.840 4.080 667.040 578.000 ;
      RECT 676.720 4.080 677.920 578.000 ;
      RECT 687.600 4.080 688.800 578.000 ;
      RECT 698.480 4.080 699.680 578.000 ;
      RECT 709.360 4.080 710.560 578.000 ;
    END
  END VSS
  PIN VDD
    DIRECTION INOUT ;
    USE POWER ;
    PORT
      LAYER met4 ;
      RECT 7.600 4.080 8.800 578.000 ;
      RECT 18.480 4.080 19.680 578.000 ;
      RECT 29.360 4.080 30.560 578.000 ;
      RECT 40.240 4.080 41.440 578.000 ;
      RECT 51.120 4.080 52.320 578.000 ;
      RECT 62.000 4.080 63.200 578.000 ;
      RECT 72.880 4.080 74.080 578.000 ;
      RECT 83.760 4.080 84.960 578.000 ;
      RECT 94.640 4.080 95.840 578.000 ;
      RECT 105.520 4.080 106.720 578.000 ;
      RECT 116.400 4.080 117.600 578.000 ;
      RECT 127.280 4.080 128.480 578.000 ;
      RECT 138.160 4.080 139.360 578.000 ;
      RECT 149.040 4.080 150.240 578.000 ;
      RECT 159.920 4.080 161.120 578.000 ;
      RECT 170.800 4.080 172.000 578.000 ;
      RECT 181.680 4.080 182.880 578.000 ;
      RECT 192.560 4.080 193.760 578.000 ;
      RECT 203.440 4.080 204.640 578.000 ;
      RECT 214.320 4.080 215.520 578.000 ;
      RECT 225.200 4.080 226.400 578.000 ;
      RECT 236.080 4.080 237.280 578.000 ;
      RECT 246.960 4.080 248.160 578.000 ;
      RECT 257.840 4.080 259.040 578.000 ;
      RECT 268.720 4.080 269.920 578.000 ;
      RECT 279.600 4.080 280.800 578.000 ;
      RECT 290.480 4.080 291.680 578.000 ;
      RECT 301.360 4.080 302.560 578.000 ;
      RECT 312.240 4.080 313.440 578.000 ;
      RECT 323.120 4.080 324.320 578.000 ;
      RECT 334.000 4.080 335.200 578.000 ;
      RECT 344.880 4.080 346.080 578.000 ;
      RECT 355.760 4.080 356.960 578.000 ;
      RECT 366.640 4.080 367.840 578.000 ;
      RECT 377.520 4.080 378.720 578.000 ;
      RECT 388.400 4.080 389.600 578.000 ;
      RECT 399.280 4.080 400.480 578.000 ;
      RECT 410.160 4.080 411.360 578.000 ;
      RECT 421.040 4.080 422.240 578.000 ;
      RECT 431.920 4.080 433.120 578.000 ;
      RECT 442.800 4.080 444.000 578.000 ;
      RECT 453.680 4.080 454.880 578.000 ;
      RECT 464.560 4.080 465.760 578.000 ;
      RECT 475.440 4.080 476.640 578.000 ;
      RECT 486.320 4.080 487.520 578.000 ;
      RECT 497.200 4.080 498.400 578.000 ;
      RECT 508.080 4.080 509.280 578.000 ;
      RECT 518.960 4.080 520.160 578.000 ;
      RECT 529.840 4.080 531.040 578.000 ;
      RECT 540.720 4.080 541.920 578.000 ;
      RECT 551.600 4.080 552.800 578.000 ;
      RECT 562.480 4.080 563.680 578.000 ;
      RECT 573.360 4.080 574.560 578.000 ;
      RECT 584.240 4.080 585.440 578.000 ;
      RECT 595.120 4.080 596.320 578.000 ;
      RECT 606.000 4.080 607.200 578.000 ;
      RECT 616.880 4.080 618.080 578.000 ;
      RECT 627.760 4.080 628.960 578.000 ;
      RECT 638.640 4.080 639.840 578.000 ;
      RECT 649.520 4.080 650.720 578.000 ;
      RECT 660.400 4.080 661.600 578.000 ;
      RECT 671.280 4.080 672.480 578.000 ;
      RECT 682.160 4.080 683.360 578.000 ;
      RECT 693.040 4.080 694.240 578.000 ;
      RECT 703.920 4.080 705.120 578.000 ;
    END
  END VDD
  OBS
    LAYER met1 ;
    RECT 0 0 715.760 582.080 ;
    LAYER met2 ;
    RECT 0 0 715.760 582.080 ;
    LAYER met3 ;
    RECT 0 0 715.760 582.080 ;
    LAYER met4 ;
    RECT 0 0 715.760 582.080 ;
  END
END fakeram_128x256_1rw

END LIBRARY
